VERSION 5.7 ;
  NOWIREEXTENSIONATPIN ON ;
  DIVIDERCHAR "/" ;
  BUSBITCHARS "[]" ;
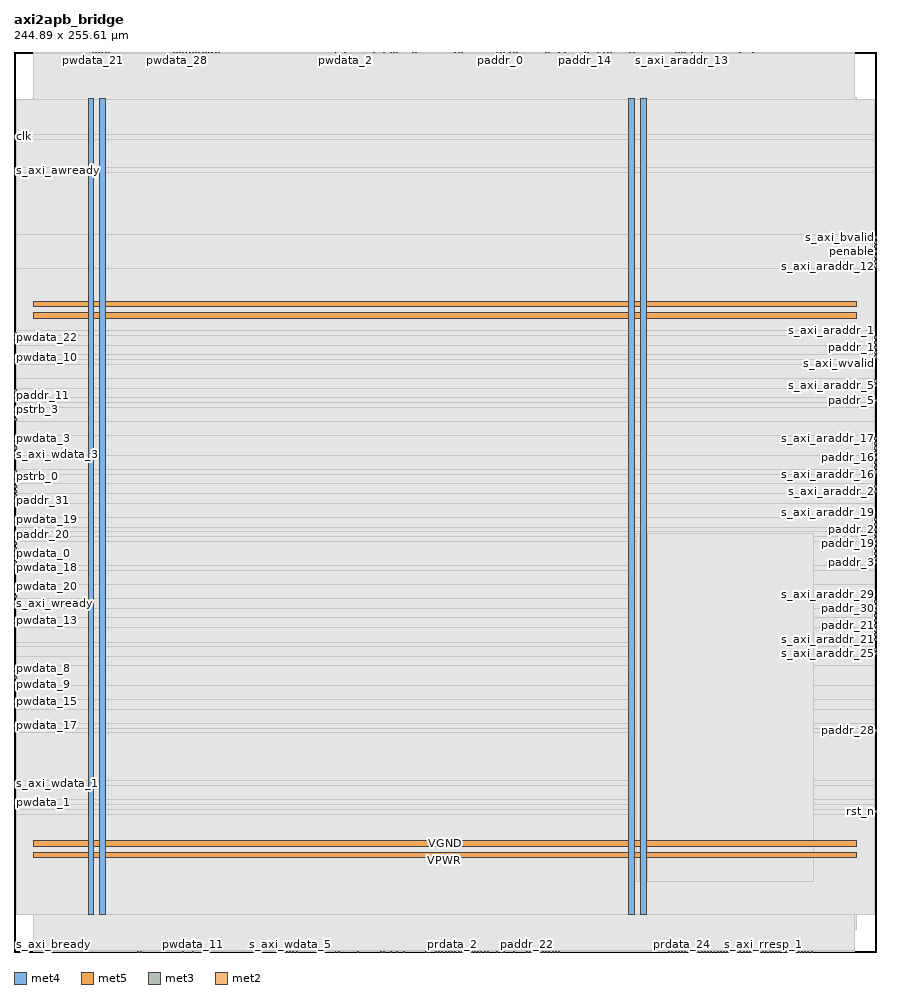
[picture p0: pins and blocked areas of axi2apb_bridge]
MACRO axi2apb_bridge
  CLASS BLOCK ;
  FOREIGN axi2apb_bridge ;
  ORIGIN 0.000 0.000 ;
  SIZE 244.890 BY 255.610 ;
  PIN VGND
    DIRECTION INOUT ;
    USE GROUND ;
    PORT
      LAYER met4 ;
        RECT 24.340 10.640 25.940 242.320 ;
    END
    PORT
      LAYER met4 ;
        RECT 177.940 10.640 179.540 242.320 ;
    END
    PORT
      LAYER met5 ;
        RECT 5.520 30.030 239.200 31.630 ;
    END
    PORT
      LAYER met5 ;
        RECT 5.520 183.210 239.200 184.810 ;
    END
  END VGND
  PIN VPWR
    DIRECTION INOUT ;
    USE POWER ;
    PORT
      LAYER met4 ;
        RECT 21.040 10.640 22.640 242.320 ;
    END
    PORT
      LAYER met4 ;
        RECT 174.640 10.640 176.240 242.320 ;
    END
    PORT
      LAYER met5 ;
        RECT 5.520 26.730 239.200 28.330 ;
    END
    PORT
      LAYER met5 ;
        RECT 5.520 179.910 239.200 181.510 ;
    END
  END VPWR
  PIN clk
    DIRECTION INPUT ;
    USE SIGNAL ;
    ANTENNAGATEAREA 1.286700 ;
    ANTENNADIFFAREA 0.434700 ;
    PORT
      LAYER met3 ;
        RECT 0.000 231.240 0.600 231.840 ;
    END
  END clk
  PIN paddr_0
    DIRECTION OUTPUT ;
    USE SIGNAL ;
    ANTENNAGATEAREA 0.434700 ;
    ANTENNADIFFAREA 1.137600 ;
    PORT
      LAYER met2 ;
        RECT 138.090 255.330 138.370 255.610 ;
    END
  END paddr_0
  PIN paddr_1
    DIRECTION OUTPUT ;
    USE SIGNAL ;
    ANTENNAGATEAREA 0.434700 ;
    ANTENNADIFFAREA 1.137600 ;
    PORT
      LAYER met3 ;
        RECT 244.290 171.400 244.890 172.000 ;
    END
  END paddr_1
  PIN paddr_10
    DIRECTION OUTPUT ;
    USE SIGNAL ;
    ANTENNAGATEAREA 0.434700 ;
    ANTENNADIFFAREA 1.137600 ;
    PORT
      LAYER met2 ;
        RECT 125.210 255.330 125.490 255.610 ;
    END
  END paddr_10
  PIN paddr_11
    DIRECTION OUTPUT ;
    USE SIGNAL ;
    ANTENNAGATEAREA 0.434700 ;
    ANTENNADIFFAREA 1.137600 ;
    PORT
      LAYER met3 ;
        RECT 0.000 157.800 0.600 158.400 ;
    END
  END paddr_11
  PIN paddr_12
    DIRECTION OUTPUT ;
    USE SIGNAL ;
    ANTENNAGATEAREA 0.434700 ;
    ANTENNADIFFAREA 1.137600 ;
    PORT
      LAYER met2 ;
        RECT 209.850 255.330 210.130 255.610 ;
    END
  END paddr_12
  PIN paddr_13
    DIRECTION OUTPUT ;
    USE SIGNAL ;
    ANTENNAGATEAREA 0.434700 ;
    ANTENNADIFFAREA 1.137600 ;
    PORT
      LAYER met2 ;
        RECT 206.170 255.330 206.450 255.610 ;
    END
  END paddr_13
  PIN paddr_14
    DIRECTION OUTPUT ;
    USE SIGNAL ;
    ANTENNAGATEAREA 0.434700 ;
    ANTENNADIFFAREA 1.137600 ;
    PORT
      LAYER met2 ;
        RECT 162.010 255.330 162.290 255.610 ;
    END
  END paddr_14
  PIN paddr_15
    DIRECTION OUTPUT ;
    USE SIGNAL ;
    ANTENNAGATEAREA 0.434700 ;
    ANTENNADIFFAREA 1.137600 ;
    PORT
      LAYER met2 ;
        RECT 151.890 255.330 152.170 255.610 ;
    END
  END paddr_15
  PIN paddr_16
    DIRECTION OUTPUT ;
    USE SIGNAL ;
    ANTENNAGATEAREA 0.434700 ;
    ANTENNADIFFAREA 1.137600 ;
    PORT
      LAYER met3 ;
        RECT 244.290 140.120 244.890 140.720 ;
    END
  END paddr_16
  PIN paddr_17
    DIRECTION OUTPUT ;
    USE SIGNAL ;
    ANTENNAGATEAREA 0.434700 ;
    ANTENNADIFFAREA 1.137600 ;
    PORT
      LAYER met2 ;
        RECT 150.970 255.330 151.250 255.610 ;
    END
  END paddr_17
  PIN paddr_18
    DIRECTION OUTPUT ;
    USE SIGNAL ;
    ANTENNAGATEAREA 0.434700 ;
    ANTENNADIFFAREA 1.137600 ;
    PORT
      LAYER met2 ;
        RECT 168.450 255.330 168.730 255.610 ;
    END
  END paddr_18
  PIN paddr_19
    DIRECTION OUTPUT ;
    USE SIGNAL ;
    ANTENNAGATEAREA 0.434700 ;
    ANTENNADIFFAREA 1.137600 ;
    PORT
      LAYER met3 ;
        RECT 244.290 115.640 244.890 116.240 ;
    END
  END paddr_19
  PIN paddr_2
    DIRECTION OUTPUT ;
    USE SIGNAL ;
    ANTENNAGATEAREA 0.434700 ;
    ANTENNADIFFAREA 1.137600 ;
    PORT
      LAYER met3 ;
        RECT 244.290 119.720 244.890 120.320 ;
    END
  END paddr_2
  PIN paddr_20
    DIRECTION OUTPUT ;
    USE SIGNAL ;
    ANTENNAGATEAREA 0.434700 ;
    ANTENNADIFFAREA 1.137600 ;
    PORT
      LAYER met3 ;
        RECT 0.000 118.360 0.600 118.960 ;
    END
  END paddr_20
  PIN paddr_21
    DIRECTION OUTPUT ;
    USE SIGNAL ;
    ANTENNAGATEAREA 0.434700 ;
    ANTENNADIFFAREA 1.137600 ;
    PORT
      LAYER met3 ;
        RECT 244.290 92.520 244.890 93.120 ;
    END
  END paddr_21
  PIN paddr_22
    DIRECTION OUTPUT ;
    USE SIGNAL ;
    ANTENNAGATEAREA 0.434700 ;
    ANTENNADIFFAREA 1.137600 ;
    PORT
      LAYER met2 ;
        RECT 145.450 0.000 145.730 0.280 ;
    END
  END paddr_22
  PIN paddr_23
    DIRECTION OUTPUT ;
    USE SIGNAL ;
    ANTENNAGATEAREA 0.434700 ;
    ANTENNADIFFAREA 1.137600 ;
    PORT
      LAYER met2 ;
        RECT 110.490 0.000 110.770 0.280 ;
    END
  END paddr_23
  PIN paddr_24
    DIRECTION OUTPUT ;
    USE SIGNAL ;
    ANTENNAGATEAREA 0.434700 ;
    ANTENNADIFFAREA 1.137600 ;
    PORT
      LAYER met2 ;
        RECT 226.410 0.000 226.690 0.280 ;
    END
  END paddr_24
  PIN paddr_25
    DIRECTION OUTPUT ;
    USE SIGNAL ;
    ANTENNAGATEAREA 0.434700 ;
    ANTENNADIFFAREA 1.137600 ;
    PORT
      LAYER met3 ;
        RECT 244.290 91.160 244.890 91.760 ;
    END
  END paddr_25
  PIN paddr_26
    DIRECTION OUTPUT ;
    USE SIGNAL ;
    ANTENNAGATEAREA 0.434700 ;
    ANTENNADIFFAREA 1.137600 ;
    PORT
      LAYER met2 ;
        RECT 91.170 0.000 91.450 0.280 ;
    END
  END paddr_26
  PIN paddr_27
    DIRECTION OUTPUT ;
    USE SIGNAL ;
    ANTENNAGATEAREA 0.434700 ;
    ANTENNADIFFAREA 1.137600 ;
    PORT
      LAYER met2 ;
        RECT 87.490 0.000 87.770 0.280 ;
    END
  END paddr_27
  PIN paddr_28
    DIRECTION OUTPUT ;
    USE SIGNAL ;
    ANTENNAGATEAREA 0.434700 ;
    ANTENNADIFFAREA 1.137600 ;
    PORT
      LAYER met3 ;
        RECT 244.290 62.600 244.890 63.200 ;
    END
  END paddr_28
  PIN paddr_29
    DIRECTION OUTPUT ;
    USE SIGNAL ;
    ANTENNAGATEAREA 0.434700 ;
    ANTENNADIFFAREA 1.137600 ;
    PORT
      LAYER met2 ;
        RECT 133.490 0.000 133.770 0.280 ;
    END
  END paddr_29
  PIN paddr_3
    DIRECTION OUTPUT ;
    USE SIGNAL ;
    ANTENNAGATEAREA 0.434700 ;
    ANTENNADIFFAREA 1.137600 ;
    PORT
      LAYER met3 ;
        RECT 244.290 110.200 244.890 110.800 ;
    END
  END paddr_3
  PIN paddr_30
    DIRECTION OUTPUT ;
    USE SIGNAL ;
    ANTENNAGATEAREA 0.434700 ;
    ANTENNADIFFAREA 1.137600 ;
    PORT
      LAYER met3 ;
        RECT 244.290 95.240 244.890 95.840 ;
    END
  END paddr_30
  PIN paddr_31
    DIRECTION OUTPUT ;
    USE SIGNAL ;
    ANTENNAGATEAREA 0.434700 ;
    ANTENNADIFFAREA 1.137600 ;
    PORT
      LAYER met3 ;
        RECT 0.000 127.880 0.600 128.480 ;
    END
  END paddr_31
  PIN paddr_4
    DIRECTION OUTPUT ;
    USE SIGNAL ;
    ANTENNAGATEAREA 0.434700 ;
    ANTENNADIFFAREA 1.137600 ;
    PORT
      LAYER met3 ;
        RECT 244.290 114.280 244.890 114.880 ;
    END
  END paddr_4
  PIN paddr_5
    DIRECTION OUTPUT ;
    USE SIGNAL ;
    ANTENNAGATEAREA 0.434700 ;
    ANTENNADIFFAREA 1.137600 ;
    PORT
      LAYER met3 ;
        RECT 244.290 156.440 244.890 157.040 ;
    END
  END paddr_5
  PIN paddr_6
    DIRECTION OUTPUT ;
    USE SIGNAL ;
    ANTENNAGATEAREA 0.434700 ;
    ANTENNADIFFAREA 1.137600 ;
    PORT
      LAYER met2 ;
        RECT 45.170 255.330 45.450 255.610 ;
    END
  END paddr_6
  PIN paddr_7
    DIRECTION OUTPUT ;
    USE SIGNAL ;
    ANTENNAGATEAREA 0.434700 ;
    ANTENNADIFFAREA 1.137600 ;
    PORT
      LAYER met2 ;
        RECT 102.210 255.330 102.490 255.610 ;
    END
  END paddr_7
  PIN paddr_8
    DIRECTION OUTPUT ;
    USE SIGNAL ;
    ANTENNAGATEAREA 0.434700 ;
    ANTENNADIFFAREA 1.137600 ;
    PORT
      LAYER met3 ;
        RECT 244.290 138.760 244.890 139.360 ;
    END
  END paddr_8
  PIN paddr_9
    DIRECTION OUTPUT ;
    USE SIGNAL ;
    ANTENNAGATEAREA 0.434700 ;
    ANTENNADIFFAREA 1.137600 ;
    PORT
      LAYER met2 ;
        RECT 142.690 255.330 142.970 255.610 ;
    END
  END paddr_9
  PIN penable
    DIRECTION OUTPUT ;
    USE SIGNAL ;
    ANTENNAGATEAREA 0.434700 ;
    ANTENNADIFFAREA 1.137600 ;
    PORT
      LAYER met3 ;
        RECT 244.290 198.600 244.890 199.200 ;
    END
  END penable
  PIN prdata_0
    DIRECTION INPUT ;
    USE SIGNAL ;
    ANTENNAGATEAREA 0.647700 ;
    ANTENNADIFFAREA 0.434700 ;
    PORT
      LAYER met2 ;
        RECT 204.330 0.000 204.610 0.280 ;
    END
  END prdata_0
  PIN prdata_1
    DIRECTION INPUT ;
    USE SIGNAL ;
    ANTENNAGATEAREA 0.647700 ;
    ANTENNADIFFAREA 0.434700 ;
    PORT
      LAYER met2 ;
        RECT 185.930 0.000 186.210 0.280 ;
    END
  END prdata_1
  PIN prdata_10
    DIRECTION INPUT ;
    USE SIGNAL ;
    ANTENNAGATEAREA 0.647700 ;
    ANTENNADIFFAREA 0.434700 ;
    PORT
      LAYER met2 ;
        RECT 132.570 0.000 132.850 0.280 ;
    END
  END prdata_10
  PIN prdata_11
    DIRECTION INPUT ;
    USE SIGNAL ;
    ANTENNAGATEAREA 0.647700 ;
    ANTENNADIFFAREA 0.434700 ;
    PORT
      LAYER met2 ;
        RECT 119.690 0.000 119.970 0.280 ;
    END
  END prdata_11
  PIN prdata_12
    DIRECTION INPUT ;
    USE SIGNAL ;
    ANTENNAGATEAREA 0.647700 ;
    ANTENNADIFFAREA 0.434700 ;
    PORT
      LAYER met2 ;
        RECT 225.490 0.000 225.770 0.280 ;
    END
  END prdata_12
  PIN prdata_13
    DIRECTION INPUT ;
    USE SIGNAL ;
    ANTENNAGATEAREA 0.647700 ;
    ANTENNADIFFAREA 0.434700 ;
    PORT
      LAYER met2 ;
        RECT 122.450 0.000 122.730 0.280 ;
    END
  END prdata_13
  PIN prdata_14
    DIRECTION INPUT ;
    USE SIGNAL ;
    ANTENNAGATEAREA 0.647700 ;
    ANTENNADIFFAREA 0.434700 ;
    PORT
      LAYER met2 ;
        RECT 127.050 0.000 127.330 0.280 ;
    END
  END prdata_14
  PIN prdata_15
    DIRECTION INPUT ;
    USE SIGNAL ;
    ANTENNAGATEAREA 0.647700 ;
    ANTENNADIFFAREA 0.434700 ;
    PORT
      LAYER met2 ;
        RECT 205.250 0.000 205.530 0.280 ;
    END
  END prdata_15
  PIN prdata_16
    DIRECTION INPUT ;
    USE SIGNAL ;
    ANTENNAGATEAREA 0.647700 ;
    ANTENNADIFFAREA 0.434700 ;
    PORT
      LAYER met2 ;
        RECT 196.050 0.000 196.330 0.280 ;
    END
  END prdata_16
  PIN prdata_17
    DIRECTION INPUT ;
    USE SIGNAL ;
    ANTENNAGATEAREA 0.647700 ;
    ANTENNADIFFAREA 0.434700 ;
    PORT
      LAYER met2 ;
        RECT 127.970 0.000 128.250 0.280 ;
    END
  END prdata_17
  PIN prdata_18
    DIRECTION INPUT ;
    USE SIGNAL ;
    ANTENNAGATEAREA 0.647700 ;
    ANTENNADIFFAREA 0.434700 ;
    PORT
      LAYER met2 ;
        RECT 203.410 0.000 203.690 0.280 ;
    END
  END prdata_18
  PIN prdata_19
    DIRECTION INPUT ;
    USE SIGNAL ;
    ANTENNAGATEAREA 0.647700 ;
    ANTENNADIFFAREA 0.434700 ;
    PORT
      LAYER met2 ;
        RECT 224.570 0.000 224.850 0.280 ;
    END
  END prdata_19
  PIN prdata_2
    DIRECTION INPUT ;
    USE SIGNAL ;
    ANTENNAGATEAREA 0.647700 ;
    ANTENNADIFFAREA 0.434700 ;
    PORT
      LAYER met2 ;
        RECT 124.290 0.000 124.570 0.280 ;
    END
  END prdata_2
  PIN prdata_20
    DIRECTION INPUT ;
    USE SIGNAL ;
    ANTENNAGATEAREA 0.647700 ;
    ANTENNADIFFAREA 0.434700 ;
    PORT
      LAYER met2 ;
        RECT 150.970 0.000 151.250 0.280 ;
    END
  END prdata_20
  PIN prdata_21
    DIRECTION INPUT ;
    USE SIGNAL ;
    ANTENNAGATEAREA 0.647700 ;
    ANTENNADIFFAREA 0.434700 ;
    PORT
      LAYER met2 ;
        RECT 194.210 0.000 194.490 0.280 ;
    END
  END prdata_21
  PIN prdata_22
    DIRECTION INPUT ;
    USE SIGNAL ;
    ANTENNAGATEAREA 0.647700 ;
    ANTENNADIFFAREA 0.434700 ;
    PORT
      LAYER met2 ;
        RECT 220.890 0.000 221.170 0.280 ;
    END
  END prdata_22
  PIN prdata_23
    DIRECTION INPUT ;
    USE SIGNAL ;
    ANTENNAGATEAREA 0.647700 ;
    ANTENNADIFFAREA 0.434700 ;
    PORT
      LAYER met2 ;
        RECT 187.770 0.000 188.050 0.280 ;
    END
  END prdata_23
  PIN prdata_24
    DIRECTION INPUT ;
    USE SIGNAL ;
    ANTENNAGATEAREA 0.647700 ;
    ANTENNADIFFAREA 0.434700 ;
    PORT
      LAYER met2 ;
        RECT 189.610 0.000 189.890 0.280 ;
    END
  END prdata_24
  PIN prdata_25
    DIRECTION INPUT ;
    USE SIGNAL ;
    ANTENNAGATEAREA 0.647700 ;
    ANTENNADIFFAREA 0.434700 ;
    PORT
      LAYER met2 ;
        RECT 199.730 0.000 200.010 0.280 ;
    END
  END prdata_25
  PIN prdata_26
    DIRECTION INPUT ;
    USE SIGNAL ;
    ANTENNAGATEAREA 0.647700 ;
    ANTENNADIFFAREA 0.434700 ;
    PORT
      LAYER met2 ;
        RECT 131.650 0.000 131.930 0.280 ;
    END
  END prdata_26
  PIN prdata_27
    DIRECTION INPUT ;
    USE SIGNAL ;
    ANTENNAGATEAREA 0.647700 ;
    ANTENNADIFFAREA 0.434700 ;
    PORT
      LAYER met2 ;
        RECT 123.370 0.000 123.650 0.280 ;
    END
  END prdata_27
  PIN prdata_28
    DIRECTION INPUT ;
    USE SIGNAL ;
    ANTENNAGATEAREA 0.647700 ;
    ANTENNADIFFAREA 0.434700 ;
    PORT
      LAYER met2 ;
        RECT 202.490 0.000 202.770 0.280 ;
    END
  END prdata_28
  PIN prdata_29
    DIRECTION INPUT ;
    USE SIGNAL ;
    ANTENNAGATEAREA 0.647700 ;
    ANTENNADIFFAREA 0.434700 ;
    PORT
      LAYER met2 ;
        RECT 208.930 0.000 209.210 0.280 ;
    END
  END prdata_29
  PIN prdata_3
    DIRECTION INPUT ;
    USE SIGNAL ;
    ANTENNAGATEAREA 0.647700 ;
    ANTENNADIFFAREA 0.434700 ;
    PORT
      LAYER met2 ;
        RECT 137.170 0.000 137.450 0.280 ;
    END
  END prdata_3
  PIN prdata_30
    DIRECTION INPUT ;
    USE SIGNAL ;
    ANTENNAGATEAREA 0.647700 ;
    ANTENNADIFFAREA 0.434700 ;
    PORT
      LAYER met2 ;
        RECT 149.130 0.000 149.410 0.280 ;
    END
  END prdata_30
  PIN prdata_31
    DIRECTION INPUT ;
    USE SIGNAL ;
    ANTENNAGATEAREA 0.647700 ;
    ANTENNADIFFAREA 0.434700 ;
    PORT
      LAYER met2 ;
        RECT 206.170 0.000 206.450 0.280 ;
    END
  END prdata_31
  PIN prdata_4
    DIRECTION INPUT ;
    USE SIGNAL ;
    ANTENNAGATEAREA 0.647700 ;
    ANTENNADIFFAREA 0.434700 ;
    PORT
      LAYER met2 ;
        RECT 147.290 0.000 147.570 0.280 ;
    END
  END prdata_4
  PIN prdata_5
    DIRECTION INPUT ;
    USE SIGNAL ;
    ANTENNAGATEAREA 0.647700 ;
    ANTENNADIFFAREA 0.434700 ;
    PORT
      LAYER met2 ;
        RECT 197.890 0.000 198.170 0.280 ;
    END
  END prdata_5
  PIN prdata_6
    DIRECTION INPUT ;
    USE SIGNAL ;
    ANTENNAGATEAREA 0.647700 ;
    ANTENNADIFFAREA 0.434700 ;
    PORT
      LAYER met2 ;
        RECT 198.810 0.000 199.090 0.280 ;
    END
  END prdata_6
  PIN prdata_7
    DIRECTION INPUT ;
    USE SIGNAL ;
    ANTENNAGATEAREA 0.647700 ;
    ANTENNADIFFAREA 0.434700 ;
    PORT
      LAYER met2 ;
        RECT 210.770 0.000 211.050 0.280 ;
    END
  END prdata_7
  PIN prdata_8
    DIRECTION INPUT ;
    USE SIGNAL ;
    ANTENNAGATEAREA 0.647700 ;
    ANTENNADIFFAREA 0.434700 ;
    PORT
      LAYER met2 ;
        RECT 154.650 0.000 154.930 0.280 ;
    END
  END prdata_8
  PIN prdata_9
    DIRECTION INPUT ;
    USE SIGNAL ;
    ANTENNAGATEAREA 0.647700 ;
    ANTENNADIFFAREA 0.434700 ;
    PORT
      LAYER met2 ;
        RECT 146.370 0.000 146.650 0.280 ;
    END
  END prdata_9
  PIN pready
    DIRECTION INPUT ;
    USE SIGNAL ;
    ANTENNAGATEAREA 0.647700 ;
    ANTENNADIFFAREA 0.434700 ;
    PORT
      LAYER met2 ;
        RECT 196.970 0.000 197.250 0.280 ;
    END
  END pready
  PIN psel_0
    DIRECTION OUTPUT ;
    USE SIGNAL ;
    ANTENNAGATEAREA 0.434700 ;
    ANTENNADIFFAREA 1.137600 ;
    PORT
      LAYER met2 ;
        RECT 188.690 255.330 188.970 255.610 ;
    END
  END psel_0
  PIN psel_1
    DIRECTION OUTPUT ;
    USE SIGNAL ;
    ANTENNAGATEAREA 0.434700 ;
    ANTENNADIFFAREA 1.137600 ;
    PORT
      LAYER met2 ;
        RECT 190.530 255.330 190.810 255.610 ;
    END
  END psel_1
  PIN psel_2
    DIRECTION OUTPUT ;
    USE SIGNAL ;
    ANTENNAGATEAREA 0.434700 ;
    ANTENNADIFFAREA 1.137600 ;
    PORT
      LAYER met2 ;
        RECT 174.890 255.330 175.170 255.610 ;
    END
  END psel_2
  PIN psel_3
    DIRECTION OUTPUT ;
    USE SIGNAL ;
    ANTENNAGATEAREA 0.434700 ;
    ANTENNADIFFAREA 1.137600 ;
    PORT
      LAYER met2 ;
        RECT 175.810 255.330 176.090 255.610 ;
    END
  END psel_3
  PIN psel_4
    DIRECTION OUTPUT ;
    USE SIGNAL ;
    ANTENNAGATEAREA 0.434700 ;
    ANTENNADIFFAREA 1.137600 ;
    PORT
      LAYER met2 ;
        RECT 192.370 255.330 192.650 255.610 ;
    END
  END psel_4
  PIN psel_5
    DIRECTION OUTPUT ;
    USE SIGNAL ;
    ANTENNAGATEAREA 0.434700 ;
    ANTENNADIFFAREA 1.137600 ;
    PORT
      LAYER met2 ;
        RECT 195.130 255.330 195.410 255.610 ;
    END
  END psel_5
  PIN pslverr
    DIRECTION INPUT ;
    USE SIGNAL ;
    ANTENNAGATEAREA 0.647700 ;
    ANTENNADIFFAREA 0.434700 ;
    PORT
      LAYER met2 ;
        RECT 219.970 0.000 220.250 0.280 ;
    END
  END pslverr
  PIN pstrb_0
    DIRECTION OUTPUT ;
    USE SIGNAL ;
    ANTENNAGATEAREA 0.434700 ;
    ANTENNADIFFAREA 1.137600 ;
    PORT
      LAYER met3 ;
        RECT 0.000 134.680 0.600 135.280 ;
    END
  END pstrb_0
  PIN pstrb_1
    DIRECTION OUTPUT ;
    USE SIGNAL ;
    ANTENNAGATEAREA 0.434700 ;
    ANTENNADIFFAREA 1.137600 ;
    PORT
      LAYER met3 ;
        RECT 0.000 131.960 0.600 132.560 ;
    END
  END pstrb_1
  PIN pstrb_2
    DIRECTION OUTPUT ;
    USE SIGNAL ;
    ANTENNAGATEAREA 0.434700 ;
    ANTENNADIFFAREA 1.137600 ;
    PORT
      LAYER met3 ;
        RECT 0.000 156.440 0.600 157.040 ;
    END
  END pstrb_2
  PIN pstrb_3
    DIRECTION OUTPUT ;
    USE SIGNAL ;
    ANTENNAGATEAREA 0.434700 ;
    ANTENNADIFFAREA 1.137600 ;
    PORT
      LAYER met3 ;
        RECT 0.000 153.720 0.600 154.320 ;
    END
  END pstrb_3
  PIN pwdata_0
    DIRECTION OUTPUT ;
    USE SIGNAL ;
    ANTENNAGATEAREA 0.434700 ;
    ANTENNADIFFAREA 1.137600 ;
    PORT
      LAYER met3 ;
        RECT 0.000 112.920 0.600 113.520 ;
    END
  END pwdata_0
  PIN pwdata_1
    DIRECTION OUTPUT ;
    USE SIGNAL ;
    ANTENNAGATEAREA 0.434700 ;
    ANTENNADIFFAREA 1.137600 ;
    PORT
      LAYER met3 ;
        RECT 0.000 42.200 0.600 42.800 ;
    END
  END pwdata_1
  PIN pwdata_10
    DIRECTION OUTPUT ;
    USE SIGNAL ;
    ANTENNAGATEAREA 0.434700 ;
    ANTENNADIFFAREA 1.137600 ;
    PORT
      LAYER met3 ;
        RECT 0.000 168.680 0.600 169.280 ;
    END
  END pwdata_10
  PIN pwdata_11
    DIRECTION OUTPUT ;
    USE SIGNAL ;
    ANTENNAGATEAREA 0.434700 ;
    ANTENNADIFFAREA 1.137600 ;
    PORT
      LAYER met2 ;
        RECT 50.690 0.000 50.970 0.280 ;
    END
  END pwdata_11
  PIN pwdata_12
    DIRECTION OUTPUT ;
    USE SIGNAL ;
    ANTENNAGATEAREA 0.434700 ;
    ANTENNADIFFAREA 1.137600 ;
    PORT
      LAYER met3 ;
        RECT 0.000 99.320 0.600 99.920 ;
    END
  END pwdata_12
  PIN pwdata_13
    DIRECTION OUTPUT ;
    USE SIGNAL ;
    ANTENNAGATEAREA 0.434700 ;
    ANTENNADIFFAREA 1.137600 ;
    PORT
      LAYER met3 ;
        RECT 0.000 93.880 0.600 94.480 ;
    END
  END pwdata_13
  PIN pwdata_14
    DIRECTION OUTPUT ;
    USE SIGNAL ;
    ANTENNAGATEAREA 0.434700 ;
    ANTENNADIFFAREA 1.137600 ;
    PORT
      LAYER met2 ;
        RECT 35.050 0.000 35.330 0.280 ;
    END
  END pwdata_14
  PIN pwdata_15
    DIRECTION OUTPUT ;
    USE SIGNAL ;
    ANTENNAGATEAREA 0.434700 ;
    ANTENNADIFFAREA 1.137600 ;
    PORT
      LAYER met3 ;
        RECT 0.000 70.760 0.600 71.360 ;
    END
  END pwdata_15
  PIN pwdata_16
    DIRECTION OUTPUT ;
    USE SIGNAL ;
    ANTENNAGATEAREA 0.434700 ;
    ANTENNADIFFAREA 1.137600 ;
    PORT
      LAYER met3 ;
        RECT 0.000 141.480 0.600 142.080 ;
    END
  END pwdata_16
  PIN pwdata_17
    DIRECTION OUTPUT ;
    USE SIGNAL ;
    ANTENNAGATEAREA 0.434700 ;
    ANTENNADIFFAREA 1.137600 ;
    PORT
      LAYER met3 ;
        RECT 0.000 63.960 0.600 64.560 ;
    END
  END pwdata_17
  PIN pwdata_18
    DIRECTION OUTPUT ;
    USE SIGNAL ;
    ANTENNAGATEAREA 0.434700 ;
    ANTENNADIFFAREA 1.137600 ;
    PORT
      LAYER met3 ;
        RECT 0.000 108.840 0.600 109.440 ;
    END
  END pwdata_18
  PIN pwdata_19
    DIRECTION OUTPUT ;
    USE SIGNAL ;
    ANTENNAGATEAREA 0.434700 ;
    ANTENNADIFFAREA 1.137600 ;
    PORT
      LAYER met3 ;
        RECT 0.000 122.440 0.600 123.040 ;
    END
  END pwdata_19
  PIN pwdata_2
    DIRECTION OUTPUT ;
    USE SIGNAL ;
    ANTENNAGATEAREA 0.434700 ;
    ANTENNADIFFAREA 1.137600 ;
    PORT
      LAYER met2 ;
        RECT 93.930 255.330 94.210 255.610 ;
    END
  END pwdata_2
  PIN pwdata_20
    DIRECTION OUTPUT ;
    USE SIGNAL ;
    ANTENNAGATEAREA 0.434700 ;
    ANTENNADIFFAREA 1.137600 ;
    PORT
      LAYER met3 ;
        RECT 0.000 103.400 0.600 104.000 ;
    END
  END pwdata_20
  PIN pwdata_21
    DIRECTION OUTPUT ;
    USE SIGNAL ;
    ANTENNAGATEAREA 0.434700 ;
    ANTENNADIFFAREA 1.137600 ;
    PORT
      LAYER met2 ;
        RECT 22.170 255.330 22.450 255.610 ;
    END
  END pwdata_21
  PIN pwdata_22
    DIRECTION OUTPUT ;
    USE SIGNAL ;
    ANTENNAGATEAREA 0.434700 ;
    ANTENNADIFFAREA 1.137600 ;
    PORT
      LAYER met3 ;
        RECT 0.000 174.120 0.600 174.720 ;
    END
  END pwdata_22
  PIN pwdata_23
    DIRECTION OUTPUT ;
    USE SIGNAL ;
    ANTENNAGATEAREA 0.434700 ;
    ANTENNADIFFAREA 1.137600 ;
    PORT
      LAYER met2 ;
        RECT 26.770 255.330 27.050 255.610 ;
    END
  END pwdata_23
  PIN pwdata_24
    DIRECTION OUTPUT ;
    USE SIGNAL ;
    ANTENNAGATEAREA 0.434700 ;
    ANTENNADIFFAREA 1.137600 ;
    PORT
      LAYER met2 ;
        RECT 25.850 255.330 26.130 255.610 ;
    END
  END pwdata_24
  PIN pwdata_25
    DIRECTION OUTPUT ;
    USE SIGNAL ;
    ANTENNAGATEAREA 0.434700 ;
    ANTENNADIFFAREA 1.137600 ;
    PORT
      LAYER met2 ;
        RECT 55.290 255.330 55.570 255.610 ;
    END
  END pwdata_25
  PIN pwdata_26
    DIRECTION OUTPUT ;
    USE SIGNAL ;
    ANTENNAGATEAREA 0.434700 ;
    ANTENNADIFFAREA 1.137600 ;
    PORT
      LAYER met2 ;
        RECT 47.010 255.330 47.290 255.610 ;
    END
  END pwdata_26
  PIN pwdata_27
    DIRECTION OUTPUT ;
    USE SIGNAL ;
    ANTENNAGATEAREA 0.434700 ;
    ANTENNADIFFAREA 1.137600 ;
    PORT
      LAYER met2 ;
        RECT 56.210 255.330 56.490 255.610 ;
    END
  END pwdata_27
  PIN pwdata_28
    DIRECTION OUTPUT ;
    USE SIGNAL ;
    ANTENNAGATEAREA 0.434700 ;
    ANTENNADIFFAREA 1.137600 ;
    PORT
      LAYER met2 ;
        RECT 46.090 255.330 46.370 255.610 ;
    END
  END pwdata_28
  PIN pwdata_29
    DIRECTION OUTPUT ;
    USE SIGNAL ;
    ANTENNAGATEAREA 0.434700 ;
    ANTENNADIFFAREA 1.137600 ;
    PORT
      LAYER met2 ;
        RECT 47.930 255.330 48.210 255.610 ;
    END
  END pwdata_29
  PIN pwdata_3
    DIRECTION OUTPUT ;
    USE SIGNAL ;
    ANTENNAGATEAREA 0.434700 ;
    ANTENNADIFFAREA 1.137600 ;
    PORT
      LAYER met3 ;
        RECT 0.000 145.560 0.600 146.160 ;
    END
  END pwdata_3
  PIN pwdata_30
    DIRECTION OUTPUT ;
    USE SIGNAL ;
    ANTENNAGATEAREA 0.434700 ;
    ANTENNADIFFAREA 1.137600 ;
    PORT
      LAYER met2 ;
        RECT 54.370 255.330 54.650 255.610 ;
    END
  END pwdata_30
  PIN pwdata_31
    DIRECTION OUTPUT ;
    USE SIGNAL ;
    ANTENNAGATEAREA 0.434700 ;
    ANTENNADIFFAREA 1.137600 ;
    PORT
      LAYER met2 ;
        RECT 49.770 255.330 50.050 255.610 ;
    END
  END pwdata_31
  PIN pwdata_4
    DIRECTION OUTPUT ;
    USE SIGNAL ;
    ANTENNAGATEAREA 0.434700 ;
    ANTENNADIFFAREA 1.137600 ;
    PORT
      LAYER met2 ;
        RECT 97.610 0.000 97.890 0.280 ;
    END
  END pwdata_4
  PIN pwdata_5
    DIRECTION OUTPUT ;
    USE SIGNAL ;
    ANTENNAGATEAREA 0.434700 ;
    ANTENNADIFFAREA 1.137600 ;
    PORT
      LAYER met2 ;
        RECT 80.130 0.000 80.410 0.280 ;
    END
  END pwdata_5
  PIN pwdata_6
    DIRECTION OUTPUT ;
    USE SIGNAL ;
    ANTENNAGATEAREA 0.434700 ;
    ANTENNADIFFAREA 1.137600 ;
    PORT
      LAYER met2 ;
        RECT 70.010 0.000 70.290 0.280 ;
    END
  END pwdata_6
  PIN pwdata_7
    DIRECTION OUTPUT ;
    USE SIGNAL ;
    ANTENNAGATEAREA 0.434700 ;
    ANTENNADIFFAREA 1.137600 ;
    PORT
      LAYER met2 ;
        RECT 77.370 0.000 77.650 0.280 ;
    END
  END pwdata_7
  PIN pwdata_8
    DIRECTION OUTPUT ;
    USE SIGNAL ;
    ANTENNAGATEAREA 0.434700 ;
    ANTENNADIFFAREA 1.137600 ;
    PORT
      LAYER met3 ;
        RECT 0.000 80.280 0.600 80.880 ;
    END
  END pwdata_8
  PIN pwdata_9
    DIRECTION OUTPUT ;
    USE SIGNAL ;
    ANTENNAGATEAREA 0.434700 ;
    ANTENNADIFFAREA 1.137600 ;
    PORT
      LAYER met3 ;
        RECT 0.000 77.560 0.600 78.160 ;
    END
  END pwdata_9
  PIN pwrite
    DIRECTION OUTPUT ;
    USE SIGNAL ;
    ANTENNAGATEAREA 0.434700 ;
    ANTENNADIFFAREA 1.137600 ;
    PORT
      LAYER met3 ;
        RECT 0.000 175.480 0.600 176.080 ;
    END
  END pwrite
  PIN rst_n
    DIRECTION INPUT ;
    USE SIGNAL ;
    ANTENNAGATEAREA 0.647700 ;
    ANTENNADIFFAREA 0.434700 ;
    PORT
      LAYER met3 ;
        RECT 244.290 39.480 244.890 40.080 ;
    END
  END rst_n
  PIN s_axi_araddr_0
    DIRECTION INPUT ;
    USE SIGNAL ;
    ANTENNAGATEAREA 0.647700 ;
    ANTENNADIFFAREA 0.434700 ;
    PORT
      LAYER met2 ;
        RECT 139.010 255.330 139.290 255.610 ;
    END
  END s_axi_araddr_0
  PIN s_axi_araddr_1
    DIRECTION INPUT ;
    USE SIGNAL ;
    ANTENNAGATEAREA 0.647700 ;
    ANTENNADIFFAREA 0.434700 ;
    PORT
      LAYER met3 ;
        RECT 244.290 174.120 244.890 174.720 ;
    END
  END s_axi_araddr_1
  PIN s_axi_araddr_10
    DIRECTION INPUT ;
    USE SIGNAL ;
    ANTENNAGATEAREA 0.647700 ;
    ANTENNADIFFAREA 0.434700 ;
    PORT
      LAYER met2 ;
        RECT 127.050 255.330 127.330 255.610 ;
    END
  END s_axi_araddr_10
  PIN s_axi_araddr_11
    DIRECTION INPUT ;
    USE SIGNAL ;
    ANTENNAGATEAREA 0.647700 ;
    ANTENNADIFFAREA 0.434700 ;
    PORT
      LAYER met2 ;
        RECT 114.170 255.330 114.450 255.610 ;
    END
  END s_axi_araddr_11
  PIN s_axi_araddr_12
    DIRECTION INPUT ;
    USE SIGNAL ;
    ANTENNAGATEAREA 0.647700 ;
    ANTENNADIFFAREA 0.434700 ;
    PORT
      LAYER met3 ;
        RECT 244.290 194.520 244.890 195.120 ;
    END
  END s_axi_araddr_12
  PIN s_axi_araddr_13
    DIRECTION INPUT ;
    USE SIGNAL ;
    ANTENNAGATEAREA 0.647700 ;
    ANTENNADIFFAREA 0.434700 ;
    PORT
      LAYER met2 ;
        RECT 189.610 255.330 189.890 255.610 ;
    END
  END s_axi_araddr_13
  PIN s_axi_araddr_14
    DIRECTION INPUT ;
    USE SIGNAL ;
    ANTENNAGATEAREA 0.647700 ;
    ANTENNADIFFAREA 0.434700 ;
    PORT
      LAYER met2 ;
        RECT 169.370 255.330 169.650 255.610 ;
    END
  END s_axi_araddr_14
  PIN s_axi_araddr_15
    DIRECTION INPUT ;
    USE SIGNAL ;
    ANTENNAGATEAREA 0.647700 ;
    ANTENNADIFFAREA 0.434700 ;
    PORT
      LAYER met2 ;
        RECT 156.490 255.330 156.770 255.610 ;
    END
  END s_axi_araddr_15
  PIN s_axi_araddr_16
    DIRECTION INPUT ;
    USE SIGNAL ;
    ANTENNAGATEAREA 0.647700 ;
    ANTENNADIFFAREA 0.434700 ;
    PORT
      LAYER met3 ;
        RECT 244.290 137.400 244.890 138.000 ;
    END
  END s_axi_araddr_16
  PIN s_axi_araddr_17
    DIRECTION INPUT ;
    USE SIGNAL ;
    ANTENNAGATEAREA 0.647700 ;
    ANTENNADIFFAREA 0.434700 ;
    PORT
      LAYER met3 ;
        RECT 244.290 145.560 244.890 146.160 ;
    END
  END s_axi_araddr_17
  PIN s_axi_araddr_18
    DIRECTION INPUT ;
    USE SIGNAL ;
    ANTENNAGATEAREA 0.647700 ;
    ANTENNADIFFAREA 0.434700 ;
    PORT
      LAYER met2 ;
        RECT 165.690 255.330 165.970 255.610 ;
    END
  END s_axi_araddr_18
  PIN s_axi_araddr_19
    DIRECTION INPUT ;
    USE SIGNAL ;
    ANTENNAGATEAREA 0.647700 ;
    ANTENNADIFFAREA 0.434700 ;
    PORT
      LAYER met3 ;
        RECT 244.290 122.440 244.890 123.040 ;
    END
  END s_axi_araddr_19
  PIN s_axi_araddr_2
    DIRECTION INPUT ;
    USE SIGNAL ;
    ANTENNAGATEAREA 0.647700 ;
    ANTENNADIFFAREA 0.434700 ;
    PORT
      LAYER met3 ;
        RECT 244.290 130.600 244.890 131.200 ;
    END
  END s_axi_araddr_2
  PIN s_axi_araddr_20
    DIRECTION INPUT ;
    USE SIGNAL ;
    ANTENNAGATEAREA 0.647700 ;
    ANTENNADIFFAREA 0.434700 ;
    PORT
      LAYER met3 ;
        RECT 0.000 115.640 0.600 116.240 ;
    END
  END s_axi_araddr_20
  PIN s_axi_araddr_21
    DIRECTION INPUT ;
    USE SIGNAL ;
    ANTENNAGATEAREA 0.647700 ;
    ANTENNADIFFAREA 0.434700 ;
    PORT
      LAYER met3 ;
        RECT 244.290 88.440 244.890 89.040 ;
    END
  END s_axi_araddr_21
  PIN s_axi_araddr_22
    DIRECTION INPUT ;
    USE SIGNAL ;
    ANTENNAGATEAREA 0.647700 ;
    ANTENNADIFFAREA 0.434700 ;
    PORT
      LAYER met2 ;
        RECT 141.770 0.000 142.050 0.280 ;
    END
  END s_axi_araddr_22
  PIN s_axi_araddr_23
    DIRECTION INPUT ;
    USE SIGNAL ;
    ANTENNAGATEAREA 0.647700 ;
    ANTENNADIFFAREA 0.434700 ;
    PORT
      LAYER met2 ;
        RECT 117.850 0.000 118.130 0.280 ;
    END
  END s_axi_araddr_23
  PIN s_axi_araddr_24
    DIRECTION INPUT ;
    USE SIGNAL ;
    ANTENNAGATEAREA 0.647700 ;
    ANTENNADIFFAREA 0.434700 ;
    PORT
      LAYER met2 ;
        RECT 211.690 0.000 211.970 0.280 ;
    END
  END s_axi_araddr_24
  PIN s_axi_araddr_25
    DIRECTION INPUT ;
    USE SIGNAL ;
    ANTENNAGATEAREA 0.647700 ;
    ANTENNADIFFAREA 0.434700 ;
    PORT
      LAYER met3 ;
        RECT 244.290 84.360 244.890 84.960 ;
    END
  END s_axi_araddr_25
  PIN s_axi_araddr_26
    DIRECTION INPUT ;
    USE SIGNAL ;
    ANTENNAGATEAREA 0.647700 ;
    ANTENNADIFFAREA 0.434700 ;
    PORT
      LAYER met2 ;
        RECT 108.650 0.000 108.930 0.280 ;
    END
  END s_axi_araddr_26
  PIN s_axi_araddr_27
    DIRECTION INPUT ;
    USE SIGNAL ;
    ANTENNAGATEAREA 0.647700 ;
    ANTENNADIFFAREA 0.434700 ;
    PORT
      LAYER met2 ;
        RECT 104.970 0.000 105.250 0.280 ;
    END
  END s_axi_araddr_27
  PIN s_axi_araddr_28
    DIRECTION INPUT ;
    USE SIGNAL ;
    ANTENNAGATEAREA 0.647700 ;
    ANTENNADIFFAREA 0.434700 ;
    PORT
      LAYER met2 ;
        RECT 221.810 0.000 222.090 0.280 ;
    END
  END s_axi_araddr_28
  PIN s_axi_araddr_29
    DIRECTION INPUT ;
    USE SIGNAL ;
    ANTENNAGATEAREA 0.647700 ;
    ANTENNADIFFAREA 0.434700 ;
    PORT
      LAYER met3 ;
        RECT 244.290 99.320 244.890 99.920 ;
    END
  END s_axi_araddr_29
  PIN s_axi_araddr_3
    DIRECTION INPUT ;
    USE SIGNAL ;
    ANTENNAGATEAREA 0.647700 ;
    ANTENNADIFFAREA 0.434700 ;
    PORT
      LAYER met3 ;
        RECT 244.290 118.360 244.890 118.960 ;
    END
  END s_axi_araddr_3
  PIN s_axi_araddr_30
    DIRECTION INPUT ;
    USE SIGNAL ;
    ANTENNAGATEAREA 0.647700 ;
    ANTENNADIFFAREA 0.434700 ;
    PORT
      LAYER met3 ;
        RECT 244.290 96.600 244.890 97.200 ;
    END
  END s_axi_araddr_30
  PIN s_axi_araddr_31
    DIRECTION INPUT ;
    USE SIGNAL ;
    ANTENNAGATEAREA 0.647700 ;
    ANTENNADIFFAREA 0.434700 ;
    PORT
      LAYER met3 ;
        RECT 0.000 133.320 0.600 133.920 ;
    END
  END s_axi_araddr_31
  PIN s_axi_araddr_4
    DIRECTION INPUT ;
    USE SIGNAL ;
    ANTENNAGATEAREA 0.647700 ;
    ANTENNADIFFAREA 0.434700 ;
    PORT
      LAYER met3 ;
        RECT 244.290 112.920 244.890 113.520 ;
    END
  END s_axi_araddr_4
  PIN s_axi_araddr_5
    DIRECTION INPUT ;
    USE SIGNAL ;
    ANTENNAGATEAREA 0.647700 ;
    ANTENNADIFFAREA 0.434700 ;
    PORT
      LAYER met3 ;
        RECT 244.290 160.520 244.890 161.120 ;
    END
  END s_axi_araddr_5
  PIN s_axi_araddr_6
    DIRECTION INPUT ;
    USE SIGNAL ;
    ANTENNAGATEAREA 0.647700 ;
    ANTENNADIFFAREA 0.434700 ;
    PORT
      LAYER met2 ;
        RECT 106.810 255.330 107.090 255.610 ;
    END
  END s_axi_araddr_6
  PIN s_axi_araddr_7
    DIRECTION INPUT ;
    USE SIGNAL ;
    ANTENNAGATEAREA 0.647700 ;
    ANTENNADIFFAREA 0.434700 ;
    PORT
      LAYER met2 ;
        RECT 108.650 255.330 108.930 255.610 ;
    END
  END s_axi_araddr_7
  PIN s_axi_araddr_8
    DIRECTION INPUT ;
    USE SIGNAL ;
    ANTENNAGATEAREA 0.647700 ;
    ANTENNADIFFAREA 0.434700 ;
    PORT
      LAYER met3 ;
        RECT 244.290 141.480 244.890 142.080 ;
    END
  END s_axi_araddr_8
  PIN s_axi_araddr_9
    DIRECTION INPUT ;
    USE SIGNAL ;
    ANTENNAGATEAREA 0.647700 ;
    ANTENNADIFFAREA 0.434700 ;
    PORT
      LAYER met2 ;
        RECT 141.770 255.330 142.050 255.610 ;
    END
  END s_axi_araddr_9
  PIN s_axi_arready
    DIRECTION OUTPUT ;
    USE SIGNAL ;
    ANTENNAGATEAREA 0.434700 ;
    ANTENNADIFFAREA 1.133700 ;
    PORT
      LAYER met3 ;
        RECT 0.000 151.000 0.600 151.600 ;
    END
  END s_axi_arready
  PIN s_axi_arvalid
    DIRECTION INPUT ;
    USE SIGNAL ;
    PORT
      LAYER met2 ;
        RECT 1.930 0.000 2.210 0.280 ;
    END
  END s_axi_arvalid
  PIN s_axi_awaddr_0
    DIRECTION INPUT ;
    USE SIGNAL ;
    ANTENNAGATEAREA 0.647700 ;
    ANTENNADIFFAREA 0.434700 ;
    PORT
      LAYER met2 ;
        RECT 137.170 255.330 137.450 255.610 ;
    END
  END s_axi_awaddr_0
  PIN s_axi_awaddr_1
    DIRECTION INPUT ;
    USE SIGNAL ;
    ANTENNAGATEAREA 0.647700 ;
    ANTENNADIFFAREA 0.434700 ;
    PORT
      LAYER met3 ;
        RECT 244.290 172.760 244.890 173.360 ;
    END
  END s_axi_awaddr_1
  PIN s_axi_awaddr_10
    DIRECTION INPUT ;
    USE SIGNAL ;
    ANTENNAGATEAREA 0.647700 ;
    ANTENNADIFFAREA 0.434700 ;
    PORT
      LAYER met2 ;
        RECT 126.130 255.330 126.410 255.610 ;
    END
  END s_axi_awaddr_10
  PIN s_axi_awaddr_11
    DIRECTION INPUT ;
    USE SIGNAL ;
    ANTENNAGATEAREA 0.647700 ;
    ANTENNADIFFAREA 0.434700 ;
    PORT
      LAYER met2 ;
        RECT 113.250 255.330 113.530 255.610 ;
    END
  END s_axi_awaddr_11
  PIN s_axi_awaddr_12
    DIRECTION INPUT ;
    USE SIGNAL ;
    ANTENNAGATEAREA 0.647700 ;
    ANTENNADIFFAREA 0.434700 ;
    PORT
      LAYER met3 ;
        RECT 244.290 195.880 244.890 196.480 ;
    END
  END s_axi_awaddr_12
  PIN s_axi_awaddr_13
    DIRECTION INPUT ;
    USE SIGNAL ;
    ANTENNAGATEAREA 0.647700 ;
    ANTENNADIFFAREA 0.434700 ;
    PORT
      LAYER met2 ;
        RECT 187.770 255.330 188.050 255.610 ;
    END
  END s_axi_awaddr_13
  PIN s_axi_awaddr_14
    DIRECTION INPUT ;
    USE SIGNAL ;
    ANTENNAGATEAREA 0.647700 ;
    ANTENNADIFFAREA 0.434700 ;
    PORT
      LAYER met2 ;
        RECT 167.530 255.330 167.810 255.610 ;
    END
  END s_axi_awaddr_14
  PIN s_axi_awaddr_15
    DIRECTION INPUT ;
    USE SIGNAL ;
    ANTENNAGATEAREA 0.647700 ;
    ANTENNADIFFAREA 0.434700 ;
    PORT
      LAYER met2 ;
        RECT 154.650 255.330 154.930 255.610 ;
    END
  END s_axi_awaddr_15
  PIN s_axi_awaddr_16
    DIRECTION INPUT ;
    USE SIGNAL ;
    ANTENNAGATEAREA 0.647700 ;
    ANTENNADIFFAREA 0.434700 ;
    PORT
      LAYER met3 ;
        RECT 244.290 136.040 244.890 136.640 ;
    END
  END s_axi_awaddr_16
  PIN s_axi_awaddr_17
    DIRECTION INPUT ;
    USE SIGNAL ;
    ANTENNAGATEAREA 0.647700 ;
    ANTENNADIFFAREA 0.434700 ;
    PORT
      LAYER met3 ;
        RECT 244.290 142.840 244.890 143.440 ;
    END
  END s_axi_awaddr_17
  PIN s_axi_awaddr_18
    DIRECTION INPUT ;
    USE SIGNAL ;
    ANTENNAGATEAREA 0.647700 ;
    ANTENNADIFFAREA 0.434700 ;
    PORT
      LAYER met2 ;
        RECT 162.930 255.330 163.210 255.610 ;
    END
  END s_axi_awaddr_18
  PIN s_axi_awaddr_19
    DIRECTION INPUT ;
    USE SIGNAL ;
    ANTENNAGATEAREA 0.647700 ;
    ANTENNADIFFAREA 0.434700 ;
    PORT
      LAYER met3 ;
        RECT 244.290 121.080 244.890 121.680 ;
    END
  END s_axi_awaddr_19
  PIN s_axi_awaddr_2
    DIRECTION INPUT ;
    USE SIGNAL ;
    ANTENNAGATEAREA 0.647700 ;
    ANTENNADIFFAREA 0.434700 ;
    PORT
      LAYER met3 ;
        RECT 244.290 131.960 244.890 132.560 ;
    END
  END s_axi_awaddr_2
  PIN s_axi_awaddr_20
    DIRECTION INPUT ;
    USE SIGNAL ;
    ANTENNAGATEAREA 0.647700 ;
    ANTENNADIFFAREA 0.434700 ;
    PORT
      LAYER met3 ;
        RECT 0.000 114.280 0.600 114.880 ;
    END
  END s_axi_awaddr_20
  PIN s_axi_awaddr_21
    DIRECTION INPUT ;
    USE SIGNAL ;
    ANTENNAGATEAREA 0.647700 ;
    ANTENNADIFFAREA 0.434700 ;
    PORT
      LAYER met3 ;
        RECT 244.290 89.800 244.890 90.400 ;
    END
  END s_axi_awaddr_21
  PIN s_axi_awaddr_22
    DIRECTION INPUT ;
    USE SIGNAL ;
    ANTENNAGATEAREA 0.647700 ;
    ANTENNADIFFAREA 0.434700 ;
    PORT
      LAYER met2 ;
        RECT 139.010 0.000 139.290 0.280 ;
    END
  END s_axi_awaddr_22
  PIN s_axi_awaddr_23
    DIRECTION INPUT ;
    USE SIGNAL ;
    ANTENNAGATEAREA 0.647700 ;
    ANTENNADIFFAREA 0.434700 ;
    PORT
      LAYER met2 ;
        RECT 116.930 0.000 117.210 0.280 ;
    END
  END s_axi_awaddr_23
  PIN s_axi_awaddr_24
    DIRECTION INPUT ;
    USE SIGNAL ;
    ANTENNAGATEAREA 0.647700 ;
    ANTENNADIFFAREA 0.434700 ;
    PORT
      LAYER met2 ;
        RECT 191.450 0.000 191.730 0.280 ;
    END
  END s_axi_awaddr_24
  PIN s_axi_awaddr_25
    DIRECTION INPUT ;
    USE SIGNAL ;
    ANTENNAGATEAREA 0.647700 ;
    ANTENNADIFFAREA 0.434700 ;
    PORT
      LAYER met3 ;
        RECT 244.290 85.720 244.890 86.320 ;
    END
  END s_axi_awaddr_25
  PIN s_axi_awaddr_26
    DIRECTION INPUT ;
    USE SIGNAL ;
    ANTENNAGATEAREA 0.647700 ;
    ANTENNADIFFAREA 0.434700 ;
    PORT
      LAYER met2 ;
        RECT 106.810 0.000 107.090 0.280 ;
    END
  END s_axi_awaddr_26
  PIN s_axi_awaddr_27
    DIRECTION INPUT ;
    USE SIGNAL ;
    ANTENNAGATEAREA 0.647700 ;
    ANTENNADIFFAREA 0.434700 ;
    PORT
      LAYER met2 ;
        RECT 104.050 0.000 104.330 0.280 ;
    END
  END s_axi_awaddr_27
  PIN s_axi_awaddr_28
    DIRECTION INPUT ;
    USE SIGNAL ;
    ANTENNAGATEAREA 0.647700 ;
    ANTENNADIFFAREA 0.434700 ;
    PORT
      LAYER met2 ;
        RECT 219.050 0.000 219.330 0.280 ;
    END
  END s_axi_awaddr_28
  PIN s_axi_awaddr_29
    DIRECTION INPUT ;
    USE SIGNAL ;
    ANTENNAGATEAREA 0.647700 ;
    ANTENNADIFFAREA 0.434700 ;
    PORT
      LAYER met3 ;
        RECT 244.290 97.960 244.890 98.560 ;
    END
  END s_axi_awaddr_29
  PIN s_axi_awaddr_3
    DIRECTION INPUT ;
    USE SIGNAL ;
    ANTENNAGATEAREA 0.647700 ;
    ANTENNADIFFAREA 0.434700 ;
    PORT
      LAYER met3 ;
        RECT 244.290 117.000 244.890 117.600 ;
    END
  END s_axi_awaddr_3
  PIN s_axi_awaddr_30
    DIRECTION INPUT ;
    USE SIGNAL ;
    ANTENNAGATEAREA 0.647700 ;
    ANTENNADIFFAREA 0.434700 ;
    PORT
      LAYER met3 ;
        RECT 244.290 93.880 244.890 94.480 ;
    END
  END s_axi_awaddr_30
  PIN s_axi_awaddr_31
    DIRECTION INPUT ;
    USE SIGNAL ;
    ANTENNAGATEAREA 0.647700 ;
    ANTENNADIFFAREA 0.434700 ;
    PORT
      LAYER met3 ;
        RECT 0.000 136.040 0.600 136.640 ;
    END
  END s_axi_awaddr_31
  PIN s_axi_awaddr_4
    DIRECTION INPUT ;
    USE SIGNAL ;
    ANTENNAGATEAREA 0.647700 ;
    ANTENNADIFFAREA 0.434700 ;
    PORT
      LAYER met3 ;
        RECT 244.290 111.560 244.890 112.160 ;
    END
  END s_axi_awaddr_4
  PIN s_axi_awaddr_5
    DIRECTION INPUT ;
    USE SIGNAL ;
    ANTENNAGATEAREA 0.647700 ;
    ANTENNADIFFAREA 0.434700 ;
    PORT
      LAYER met3 ;
        RECT 244.290 161.880 244.890 162.480 ;
    END
  END s_axi_awaddr_5
  PIN s_axi_awaddr_6
    DIRECTION INPUT ;
    USE SIGNAL ;
    ANTENNAGATEAREA 0.647700 ;
    ANTENNADIFFAREA 0.434700 ;
    PORT
      LAYER met2 ;
        RECT 104.970 255.330 105.250 255.610 ;
    END
  END s_axi_awaddr_6
  PIN s_axi_awaddr_7
    DIRECTION INPUT ;
    USE SIGNAL ;
    ANTENNAGATEAREA 0.647700 ;
    ANTENNADIFFAREA 0.434700 ;
    PORT
      LAYER met2 ;
        RECT 107.730 255.330 108.010 255.610 ;
    END
  END s_axi_awaddr_7
  PIN s_axi_awaddr_8
    DIRECTION INPUT ;
    USE SIGNAL ;
    ANTENNAGATEAREA 0.647700 ;
    ANTENNADIFFAREA 0.434700 ;
    PORT
      LAYER met3 ;
        RECT 244.290 144.200 244.890 144.800 ;
    END
  END s_axi_awaddr_8
  PIN s_axi_awaddr_9
    DIRECTION INPUT ;
    USE SIGNAL ;
    ANTENNAGATEAREA 0.647700 ;
    ANTENNADIFFAREA 0.434700 ;
    PORT
      LAYER met2 ;
        RECT 140.850 255.330 141.130 255.610 ;
    END
  END s_axi_awaddr_9
  PIN s_axi_awready
    DIRECTION OUTPUT ;
    USE SIGNAL ;
    ANTENNAGATEAREA 0.434700 ;
    ANTENNADIFFAREA 0.832300 ;
    PORT
      LAYER met3 ;
        RECT 0.000 221.720 0.600 222.320 ;
    END
  END s_axi_awready
  PIN s_axi_awvalid
    DIRECTION INPUT ;
    USE SIGNAL ;
    ANTENNAGATEAREA 0.647700 ;
    ANTENNADIFFAREA 0.434700 ;
    PORT
      LAYER met3 ;
        RECT 244.290 170.040 244.890 170.640 ;
    END
  END s_axi_awvalid
  PIN s_axi_bready
    DIRECTION INPUT ;
    USE SIGNAL ;
    PORT
      LAYER met2 ;
        RECT 2.850 0.000 3.130 0.280 ;
    END
  END s_axi_bready
  PIN s_axi_bresp_0
    DIRECTION OUTPUT ;
    USE SIGNAL ;
    ANTENNAGATEAREA 0.434700 ;
    ANTENNADIFFAREA 0.434700 ;
    PORT
      LAYER met3 ;
        RECT 244.290 197.240 244.890 197.840 ;
    END
  END s_axi_bresp_0
  PIN s_axi_bresp_1
    DIRECTION OUTPUT ;
    USE SIGNAL ;
    ANTENNAGATEAREA 0.434700 ;
    ANTENNADIFFAREA 1.137600 ;
    PORT
      LAYER met2 ;
        RECT 214.450 0.000 214.730 0.280 ;
    END
  END s_axi_bresp_1
  PIN s_axi_bvalid
    DIRECTION OUTPUT ;
    USE SIGNAL ;
    ANTENNAGATEAREA 0.434700 ;
    ANTENNADIFFAREA 0.775300 ;
    PORT
      LAYER met3 ;
        RECT 244.290 202.680 244.890 203.280 ;
    END
  END s_axi_bvalid
  PIN s_axi_rdata_0
    DIRECTION OUTPUT ;
    USE SIGNAL ;
    ANTENNAGATEAREA 0.434700 ;
    ANTENNADIFFAREA 1.137600 ;
    PORT
      LAYER met2 ;
        RECT 209.850 0.000 210.130 0.280 ;
    END
  END s_axi_rdata_0
  PIN s_axi_rdata_1
    DIRECTION OUTPUT ;
    USE SIGNAL ;
    ANTENNAGATEAREA 0.434700 ;
    ANTENNADIFFAREA 1.137600 ;
    PORT
      LAYER met2 ;
        RECT 190.530 0.000 190.810 0.280 ;
    END
  END s_axi_rdata_1
  PIN s_axi_rdata_10
    DIRECTION OUTPUT ;
    USE SIGNAL ;
    ANTENNAGATEAREA 0.434700 ;
    ANTENNADIFFAREA 1.137600 ;
    PORT
      LAYER met2 ;
        RECT 130.730 0.000 131.010 0.280 ;
    END
  END s_axi_rdata_10
  PIN s_axi_rdata_11
    DIRECTION OUTPUT ;
    USE SIGNAL ;
    ANTENNAGATEAREA 0.434700 ;
    ANTENNADIFFAREA 1.137600 ;
    PORT
      LAYER met2 ;
        RECT 125.210 0.000 125.490 0.280 ;
    END
  END s_axi_rdata_11
  PIN s_axi_rdata_12
    DIRECTION OUTPUT ;
    USE SIGNAL ;
    ANTENNAGATEAREA 0.434700 ;
    ANTENNADIFFAREA 1.137600 ;
    PORT
      LAYER met2 ;
        RECT 213.530 0.000 213.810 0.280 ;
    END
  END s_axi_rdata_12
  PIN s_axi_rdata_13
    DIRECTION OUTPUT ;
    USE SIGNAL ;
    ANTENNAGATEAREA 0.434700 ;
    ANTENNADIFFAREA 1.137600 ;
    PORT
      LAYER met2 ;
        RECT 126.130 0.000 126.410 0.280 ;
    END
  END s_axi_rdata_13
  PIN s_axi_rdata_14
    DIRECTION OUTPUT ;
    USE SIGNAL ;
    ANTENNAGATEAREA 0.434700 ;
    ANTENNADIFFAREA 1.137600 ;
    PORT
      LAYER met2 ;
        RECT 128.890 0.000 129.170 0.280 ;
    END
  END s_axi_rdata_14
  PIN s_axi_rdata_15
    DIRECTION OUTPUT ;
    USE SIGNAL ;
    ANTENNAGATEAREA 0.434700 ;
    ANTENNADIFFAREA 1.137600 ;
    PORT
      LAYER met2 ;
        RECT 201.570 0.000 201.850 0.280 ;
    END
  END s_axi_rdata_15
  PIN s_axi_rdata_16
    DIRECTION OUTPUT ;
    USE SIGNAL ;
    ANTENNAGATEAREA 0.434700 ;
    ANTENNADIFFAREA 1.137600 ;
    PORT
      LAYER met2 ;
        RECT 222.730 0.000 223.010 0.280 ;
    END
  END s_axi_rdata_16
  PIN s_axi_rdata_17
    DIRECTION OUTPUT ;
    USE SIGNAL ;
    ANTENNAGATEAREA 0.434700 ;
    ANTENNADIFFAREA 1.137600 ;
    PORT
      LAYER met2 ;
        RECT 129.810 0.000 130.090 0.280 ;
    END
  END s_axi_rdata_17
  PIN s_axi_rdata_18
    DIRECTION OUTPUT ;
    USE SIGNAL ;
    ANTENNAGATEAREA 0.434700 ;
    ANTENNADIFFAREA 1.137600 ;
    PORT
      LAYER met2 ;
        RECT 208.010 0.000 208.290 0.280 ;
    END
  END s_axi_rdata_18
  PIN s_axi_rdata_19
    DIRECTION OUTPUT ;
    USE SIGNAL ;
    ANTENNAGATEAREA 0.434700 ;
    ANTENNADIFFAREA 1.137600 ;
    PORT
      LAYER met2 ;
        RECT 186.850 0.000 187.130 0.280 ;
    END
  END s_axi_rdata_19
  PIN s_axi_rdata_2
    DIRECTION OUTPUT ;
    USE SIGNAL ;
    ANTENNAGATEAREA 0.434700 ;
    ANTENNADIFFAREA 1.137600 ;
    PORT
      LAYER met2 ;
        RECT 121.530 0.000 121.810 0.280 ;
    END
  END s_axi_rdata_2
  PIN s_axi_rdata_20
    DIRECTION OUTPUT ;
    USE SIGNAL ;
    ANTENNAGATEAREA 0.434700 ;
    ANTENNADIFFAREA 1.137600 ;
    PORT
      LAYER met2 ;
        RECT 151.890 0.000 152.170 0.280 ;
    END
  END s_axi_rdata_20
  PIN s_axi_rdata_21
    DIRECTION OUTPUT ;
    USE SIGNAL ;
    ANTENNAGATEAREA 0.434700 ;
    ANTENNADIFFAREA 1.137600 ;
    PORT
      LAYER met2 ;
        RECT 215.370 0.000 215.650 0.280 ;
    END
  END s_axi_rdata_21
  PIN s_axi_rdata_22
    DIRECTION OUTPUT ;
    USE SIGNAL ;
    ANTENNAGATEAREA 0.434700 ;
    ANTENNADIFFAREA 1.137600 ;
    PORT
      LAYER met2 ;
        RECT 195.130 0.000 195.410 0.280 ;
    END
  END s_axi_rdata_22
  PIN s_axi_rdata_23
    DIRECTION OUTPUT ;
    USE SIGNAL ;
    ANTENNAGATEAREA 0.434700 ;
    ANTENNADIFFAREA 1.137600 ;
    PORT
      LAYER met2 ;
        RECT 188.690 0.000 188.970 0.280 ;
    END
  END s_axi_rdata_23
  PIN s_axi_rdata_24
    DIRECTION OUTPUT ;
    USE SIGNAL ;
    ANTENNAGATEAREA 0.434700 ;
    ANTENNADIFFAREA 1.137600 ;
    PORT
      LAYER met2 ;
        RECT 216.290 0.000 216.570 0.280 ;
    END
  END s_axi_rdata_24
  PIN s_axi_rdata_25
    DIRECTION OUTPUT ;
    USE SIGNAL ;
    ANTENNAGATEAREA 0.434700 ;
    ANTENNADIFFAREA 1.137600 ;
    PORT
      LAYER met2 ;
        RECT 192.370 0.000 192.650 0.280 ;
    END
  END s_axi_rdata_25
  PIN s_axi_rdata_26
    DIRECTION OUTPUT ;
    USE SIGNAL ;
    ANTENNAGATEAREA 0.434700 ;
    ANTENNADIFFAREA 1.137600 ;
    PORT
      LAYER met2 ;
        RECT 134.410 0.000 134.690 0.280 ;
    END
  END s_axi_rdata_26
  PIN s_axi_rdata_27
    DIRECTION OUTPUT ;
    USE SIGNAL ;
    ANTENNAGATEAREA 0.434700 ;
    ANTENNADIFFAREA 1.137600 ;
    PORT
      LAYER met2 ;
        RECT 120.610 0.000 120.890 0.280 ;
    END
  END s_axi_rdata_27
  PIN s_axi_rdata_28
    DIRECTION OUTPUT ;
    USE SIGNAL ;
    ANTENNAGATEAREA 0.434700 ;
    ANTENNADIFFAREA 1.137600 ;
    PORT
      LAYER met2 ;
        RECT 218.130 0.000 218.410 0.280 ;
    END
  END s_axi_rdata_28
  PIN s_axi_rdata_29
    DIRECTION OUTPUT ;
    USE SIGNAL ;
    ANTENNAGATEAREA 0.434700 ;
    ANTENNADIFFAREA 1.137600 ;
    PORT
      LAYER met2 ;
        RECT 223.650 0.000 223.930 0.280 ;
    END
  END s_axi_rdata_29
  PIN s_axi_rdata_3
    DIRECTION OUTPUT ;
    USE SIGNAL ;
    ANTENNAGATEAREA 0.434700 ;
    ANTENNADIFFAREA 1.137600 ;
    PORT
      LAYER met2 ;
        RECT 138.090 0.000 138.370 0.280 ;
    END
  END s_axi_rdata_3
  PIN s_axi_rdata_30
    DIRECTION OUTPUT ;
    USE SIGNAL ;
    ANTENNAGATEAREA 0.434700 ;
    ANTENNADIFFAREA 1.137600 ;
    PORT
      LAYER met2 ;
        RECT 153.730 0.000 154.010 0.280 ;
    END
  END s_axi_rdata_30
  PIN s_axi_rdata_31
    DIRECTION OUTPUT ;
    USE SIGNAL ;
    ANTENNAGATEAREA 0.434700 ;
    ANTENNADIFFAREA 1.137600 ;
    PORT
      LAYER met2 ;
        RECT 200.650 0.000 200.930 0.280 ;
    END
  END s_axi_rdata_31
  PIN s_axi_rdata_4
    DIRECTION OUTPUT ;
    USE SIGNAL ;
    ANTENNAGATEAREA 0.434700 ;
    ANTENNADIFFAREA 1.137600 ;
    PORT
      LAYER met2 ;
        RECT 148.210 0.000 148.490 0.280 ;
    END
  END s_axi_rdata_4
  PIN s_axi_rdata_5
    DIRECTION OUTPUT ;
    USE SIGNAL ;
    ANTENNAGATEAREA 0.434700 ;
    ANTENNADIFFAREA 1.137600 ;
    PORT
      LAYER met2 ;
        RECT 207.090 0.000 207.370 0.280 ;
    END
  END s_axi_rdata_5
  PIN s_axi_rdata_6
    DIRECTION OUTPUT ;
    USE SIGNAL ;
    ANTENNAGATEAREA 0.434700 ;
    ANTENNADIFFAREA 1.137600 ;
    PORT
      LAYER met2 ;
        RECT 217.210 0.000 217.490 0.280 ;
    END
  END s_axi_rdata_6
  PIN s_axi_rdata_7
    DIRECTION OUTPUT ;
    USE SIGNAL ;
    ANTENNAGATEAREA 0.434700 ;
    ANTENNADIFFAREA 1.137600 ;
    PORT
      LAYER met2 ;
        RECT 193.290 0.000 193.570 0.280 ;
    END
  END s_axi_rdata_7
  PIN s_axi_rdata_8
    DIRECTION OUTPUT ;
    USE SIGNAL ;
    ANTENNAGATEAREA 0.434700 ;
    ANTENNADIFFAREA 1.137600 ;
    PORT
      LAYER met2 ;
        RECT 152.810 0.000 153.090 0.280 ;
    END
  END s_axi_rdata_8
  PIN s_axi_rdata_9
    DIRECTION OUTPUT ;
    USE SIGNAL ;
    ANTENNAGATEAREA 0.434700 ;
    ANTENNADIFFAREA 1.137600 ;
    PORT
      LAYER met2 ;
        RECT 150.050 0.000 150.330 0.280 ;
    END
  END s_axi_rdata_9
  PIN s_axi_rready
    DIRECTION INPUT ;
    USE SIGNAL ;
    PORT
      LAYER met2 ;
        RECT 3.770 0.000 4.050 0.280 ;
    END
  END s_axi_rready
  PIN s_axi_rresp_0
    DIRECTION OUTPUT ;
    USE SIGNAL ;
    ANTENNAGATEAREA 0.434700 ;
    ANTENNADIFFAREA 0.775300 ;
    PORT
      LAYER met3 ;
        RECT 244.290 201.320 244.890 201.920 ;
    END
  END s_axi_rresp_0
  PIN s_axi_rresp_1
    DIRECTION OUTPUT ;
    USE SIGNAL ;
    ANTENNAGATEAREA 0.434700 ;
    ANTENNADIFFAREA 1.137600 ;
    PORT
      LAYER met2 ;
        RECT 212.610 0.000 212.890 0.280 ;
    END
  END s_axi_rresp_1
  PIN s_axi_rvalid
    DIRECTION OUTPUT ;
    USE SIGNAL ;
    ANTENNAGATEAREA 0.434700 ;
    ANTENNADIFFAREA 0.775300 ;
    PORT
      LAYER met3 ;
        RECT 244.290 199.960 244.890 200.560 ;
    END
  END s_axi_rvalid
  PIN s_axi_wdata_0
    DIRECTION INPUT ;
    USE SIGNAL ;
    ANTENNAGATEAREA 0.647700 ;
    ANTENNADIFFAREA 0.434700 ;
    PORT
      LAYER met3 ;
        RECT 0.000 111.560 0.600 112.160 ;
    END
  END s_axi_wdata_0
  PIN s_axi_wdata_1
    DIRECTION INPUT ;
    USE SIGNAL ;
    ANTENNAGATEAREA 0.647700 ;
    ANTENNADIFFAREA 0.434700 ;
    PORT
      LAYER met3 ;
        RECT 0.000 47.640 0.600 48.240 ;
    END
  END s_axi_wdata_1
  PIN s_axi_wdata_10
    DIRECTION INPUT ;
    USE SIGNAL ;
    ANTENNAGATEAREA 0.647700 ;
    ANTENNADIFFAREA 0.434700 ;
    PORT
      LAYER met3 ;
        RECT 0.000 167.320 0.600 167.920 ;
    END
  END s_axi_wdata_10
  PIN s_axi_wdata_11
    DIRECTION INPUT ;
    USE SIGNAL ;
    ANTENNAGATEAREA 0.647700 ;
    ANTENNADIFFAREA 0.434700 ;
    PORT
      LAYER met2 ;
        RECT 47.930 0.000 48.210 0.280 ;
    END
  END s_axi_wdata_11
  PIN s_axi_wdata_12
    DIRECTION INPUT ;
    USE SIGNAL ;
    ANTENNAGATEAREA 0.647700 ;
    ANTENNADIFFAREA 0.434700 ;
    PORT
      LAYER met3 ;
        RECT 0.000 97.960 0.600 98.560 ;
    END
  END s_axi_wdata_12
  PIN s_axi_wdata_13
    DIRECTION INPUT ;
    USE SIGNAL ;
    ANTENNAGATEAREA 0.647700 ;
    ANTENNADIFFAREA 0.434700 ;
    PORT
      LAYER met3 ;
        RECT 0.000 92.520 0.600 93.120 ;
    END
  END s_axi_wdata_13
  PIN s_axi_wdata_14
    DIRECTION INPUT ;
    USE SIGNAL ;
    ANTENNAGATEAREA 0.647700 ;
    ANTENNADIFFAREA 0.434700 ;
    PORT
      LAYER met2 ;
        RECT 35.970 0.000 36.250 0.280 ;
    END
  END s_axi_wdata_14
  PIN s_axi_wdata_15
    DIRECTION INPUT ;
    USE SIGNAL ;
    ANTENNAGATEAREA 0.647700 ;
    ANTENNADIFFAREA 0.434700 ;
    PORT
      LAYER met3 ;
        RECT 0.000 69.400 0.600 70.000 ;
    END
  END s_axi_wdata_15
  PIN s_axi_wdata_16
    DIRECTION INPUT ;
    USE SIGNAL ;
    ANTENNAGATEAREA 0.647700 ;
    ANTENNADIFFAREA 0.434700 ;
    PORT
      LAYER met3 ;
        RECT 0.000 144.200 0.600 144.800 ;
    END
  END s_axi_wdata_16
  PIN s_axi_wdata_17
    DIRECTION INPUT ;
    USE SIGNAL ;
    ANTENNAGATEAREA 0.647700 ;
    ANTENNADIFFAREA 0.434700 ;
    PORT
      LAYER met3 ;
        RECT 0.000 62.600 0.600 63.200 ;
    END
  END s_axi_wdata_17
  PIN s_axi_wdata_18
    DIRECTION INPUT ;
    USE SIGNAL ;
    ANTENNAGATEAREA 0.647700 ;
    ANTENNADIFFAREA 0.434700 ;
    PORT
      LAYER met3 ;
        RECT 0.000 110.200 0.600 110.800 ;
    END
  END s_axi_wdata_18
  PIN s_axi_wdata_19
    DIRECTION INPUT ;
    USE SIGNAL ;
    ANTENNAGATEAREA 0.647700 ;
    ANTENNADIFFAREA 0.434700 ;
    PORT
      LAYER met3 ;
        RECT 0.000 121.080 0.600 121.680 ;
    END
  END s_axi_wdata_19
  PIN s_axi_wdata_2
    DIRECTION INPUT ;
    USE SIGNAL ;
    ANTENNAGATEAREA 0.647700 ;
    ANTENNADIFFAREA 0.434700 ;
    PORT
      LAYER met2 ;
        RECT 91.170 255.330 91.450 255.610 ;
    END
  END s_axi_wdata_2
  PIN s_axi_wdata_20
    DIRECTION INPUT ;
    USE SIGNAL ;
    ANTENNAGATEAREA 0.647700 ;
    ANTENNADIFFAREA 0.434700 ;
    PORT
      LAYER met3 ;
        RECT 0.000 102.040 0.600 102.640 ;
    END
  END s_axi_wdata_20
  PIN s_axi_wdata_21
    DIRECTION INPUT ;
    USE SIGNAL ;
    ANTENNAGATEAREA 0.647700 ;
    ANTENNADIFFAREA 0.434700 ;
    PORT
      LAYER met2 ;
        RECT 24.930 255.330 25.210 255.610 ;
    END
  END s_axi_wdata_21
  PIN s_axi_wdata_22
    DIRECTION INPUT ;
    USE SIGNAL ;
    ANTENNAGATEAREA 0.647700 ;
    ANTENNADIFFAREA 0.434700 ;
    PORT
      LAYER met3 ;
        RECT 0.000 172.760 0.600 173.360 ;
    END
  END s_axi_wdata_22
  PIN s_axi_wdata_23
    DIRECTION INPUT ;
    USE SIGNAL ;
    ANTENNAGATEAREA 0.647700 ;
    ANTENNADIFFAREA 0.434700 ;
    PORT
      LAYER met2 ;
        RECT 23.090 255.330 23.370 255.610 ;
    END
  END s_axi_wdata_23
  PIN s_axi_wdata_24
    DIRECTION INPUT ;
    USE SIGNAL ;
    ANTENNAGATEAREA 0.647700 ;
    ANTENNADIFFAREA 0.434700 ;
    PORT
      LAYER met2 ;
        RECT 24.010 255.330 24.290 255.610 ;
    END
  END s_axi_wdata_24
  PIN s_axi_wdata_25
    DIRECTION INPUT ;
    USE SIGNAL ;
    ANTENNAGATEAREA 0.647700 ;
    ANTENNADIFFAREA 0.434700 ;
    PORT
      LAYER met2 ;
        RECT 57.130 255.330 57.410 255.610 ;
    END
  END s_axi_wdata_25
  PIN s_axi_wdata_26
    DIRECTION INPUT ;
    USE SIGNAL ;
    ANTENNAGATEAREA 0.647700 ;
    ANTENNADIFFAREA 0.434700 ;
    PORT
      LAYER met2 ;
        RECT 51.610 255.330 51.890 255.610 ;
    END
  END s_axi_wdata_26
  PIN s_axi_wdata_27
    DIRECTION INPUT ;
    USE SIGNAL ;
    ANTENNAGATEAREA 0.647700 ;
    ANTENNADIFFAREA 0.434700 ;
    PORT
      LAYER met2 ;
        RECT 53.450 255.330 53.730 255.610 ;
    END
  END s_axi_wdata_27
  PIN s_axi_wdata_28
    DIRECTION INPUT ;
    USE SIGNAL ;
    ANTENNAGATEAREA 0.647700 ;
    ANTENNADIFFAREA 0.434700 ;
    PORT
      LAYER met2 ;
        RECT 58.050 255.330 58.330 255.610 ;
    END
  END s_axi_wdata_28
  PIN s_axi_wdata_29
    DIRECTION INPUT ;
    USE SIGNAL ;
    ANTENNAGATEAREA 0.647700 ;
    ANTENNADIFFAREA 0.434700 ;
    PORT
      LAYER met2 ;
        RECT 48.850 255.330 49.130 255.610 ;
    END
  END s_axi_wdata_29
  PIN s_axi_wdata_3
    DIRECTION INPUT ;
    USE SIGNAL ;
    ANTENNAGATEAREA 0.647700 ;
    ANTENNADIFFAREA 0.434700 ;
    PORT
      LAYER met3 ;
        RECT 0.000 142.840 0.600 143.440 ;
    END
  END s_axi_wdata_3
  PIN s_axi_wdata_30
    DIRECTION INPUT ;
    USE SIGNAL ;
    ANTENNAGATEAREA 0.647700 ;
    ANTENNADIFFAREA 0.434700 ;
    PORT
      LAYER met2 ;
        RECT 52.530 255.330 52.810 255.610 ;
    END
  END s_axi_wdata_30
  PIN s_axi_wdata_31
    DIRECTION INPUT ;
    USE SIGNAL ;
    ANTENNAGATEAREA 0.647700 ;
    ANTENNADIFFAREA 0.434700 ;
    PORT
      LAYER met2 ;
        RECT 50.690 255.330 50.970 255.610 ;
    END
  END s_axi_wdata_31
  PIN s_axi_wdata_4
    DIRECTION INPUT ;
    USE SIGNAL ;
    ANTENNAGATEAREA 0.647700 ;
    ANTENNADIFFAREA 0.434700 ;
    PORT
      LAYER met2 ;
        RECT 92.090 0.000 92.370 0.280 ;
    END
  END s_axi_wdata_4
  PIN s_axi_wdata_5
    DIRECTION INPUT ;
    USE SIGNAL ;
    ANTENNAGATEAREA 0.647700 ;
    ANTENNADIFFAREA 0.434700 ;
    PORT
      LAYER met2 ;
        RECT 78.290 0.000 78.570 0.280 ;
    END
  END s_axi_wdata_5
  PIN s_axi_wdata_6
    DIRECTION INPUT ;
    USE SIGNAL ;
    ANTENNAGATEAREA 0.647700 ;
    ANTENNADIFFAREA 0.434700 ;
    PORT
      LAYER met2 ;
        RECT 69.090 0.000 69.370 0.280 ;
    END
  END s_axi_wdata_6
  PIN s_axi_wdata_7
    DIRECTION INPUT ;
    USE SIGNAL ;
    ANTENNAGATEAREA 0.647700 ;
    ANTENNADIFFAREA 0.434700 ;
    PORT
      LAYER met2 ;
        RECT 79.210 0.000 79.490 0.280 ;
    END
  END s_axi_wdata_7
  PIN s_axi_wdata_8
    DIRECTION INPUT ;
    USE SIGNAL ;
    ANTENNAGATEAREA 0.647700 ;
    ANTENNADIFFAREA 0.434700 ;
    PORT
      LAYER met3 ;
        RECT 0.000 78.920 0.600 79.520 ;
    END
  END s_axi_wdata_8
  PIN s_axi_wdata_9
    DIRECTION INPUT ;
    USE SIGNAL ;
    ANTENNAGATEAREA 0.647700 ;
    ANTENNADIFFAREA 0.434700 ;
    PORT
      LAYER met3 ;
        RECT 0.000 76.200 0.600 76.800 ;
    END
  END s_axi_wdata_9
  PIN s_axi_wready
    DIRECTION OUTPUT ;
    USE SIGNAL ;
    ANTENNAGATEAREA 0.434700 ;
    ANTENNADIFFAREA 0.832300 ;
    PORT
      LAYER met3 ;
        RECT 0.000 100.680 0.600 101.280 ;
    END
  END s_axi_wready
  PIN s_axi_wstrb_0
    DIRECTION INPUT ;
    USE SIGNAL ;
    ANTENNAGATEAREA 0.647700 ;
    ANTENNADIFFAREA 0.434700 ;
    PORT
      LAYER met3 ;
        RECT 0.000 130.600 0.600 131.200 ;
    END
  END s_axi_wstrb_0
  PIN s_axi_wstrb_1
    DIRECTION INPUT ;
    USE SIGNAL ;
    ANTENNAGATEAREA 0.647700 ;
    ANTENNADIFFAREA 0.434700 ;
    PORT
      LAYER met3 ;
        RECT 0.000 129.240 0.600 129.840 ;
    END
  END s_axi_wstrb_1
  PIN s_axi_wstrb_2
    DIRECTION INPUT ;
    USE SIGNAL ;
    ANTENNAGATEAREA 0.647700 ;
    ANTENNADIFFAREA 0.434700 ;
    PORT
      LAYER met3 ;
        RECT 0.000 159.160 0.600 159.760 ;
    END
  END s_axi_wstrb_2
  PIN s_axi_wstrb_3
    DIRECTION INPUT ;
    USE SIGNAL ;
    ANTENNAGATEAREA 0.647700 ;
    ANTENNADIFFAREA 0.434700 ;
    PORT
      LAYER met3 ;
        RECT 0.000 152.360 0.600 152.960 ;
    END
  END s_axi_wstrb_3
  PIN s_axi_wvalid
    DIRECTION INPUT ;
    USE SIGNAL ;
    ANTENNAGATEAREA 0.647700 ;
    ANTENNADIFFAREA 0.434700 ;
    PORT
      LAYER met3 ;
        RECT 244.290 168.680 244.890 169.280 ;
    END
  END s_axi_wvalid
  OBS
      LAYER nwell ;
        RECT 5.330 10.795 239.390 242.270 ;
      LAYER li1 ;
        RECT 5.520 10.795 239.200 242.165 ;
      LAYER met1 ;
        RECT 5.520 6.500 239.200 242.720 ;
      LAYER met2 ;
        RECT 5.610 255.050 21.890 255.330 ;
        RECT 22.730 255.050 22.810 255.330 ;
        RECT 23.650 255.050 23.730 255.330 ;
        RECT 24.570 255.050 24.650 255.330 ;
        RECT 25.490 255.050 25.570 255.330 ;
        RECT 26.410 255.050 26.490 255.330 ;
        RECT 27.330 255.050 44.890 255.330 ;
        RECT 45.730 255.050 45.810 255.330 ;
        RECT 46.650 255.050 46.730 255.330 ;
        RECT 47.570 255.050 47.650 255.330 ;
        RECT 48.490 255.050 48.570 255.330 ;
        RECT 49.410 255.050 49.490 255.330 ;
        RECT 50.330 255.050 50.410 255.330 ;
        RECT 51.250 255.050 51.330 255.330 ;
        RECT 52.170 255.050 52.250 255.330 ;
        RECT 53.090 255.050 53.170 255.330 ;
        RECT 54.010 255.050 54.090 255.330 ;
        RECT 54.930 255.050 55.010 255.330 ;
        RECT 55.850 255.050 55.930 255.330 ;
        RECT 56.770 255.050 56.850 255.330 ;
        RECT 57.690 255.050 57.770 255.330 ;
        RECT 58.610 255.050 90.890 255.330 ;
        RECT 91.730 255.050 93.650 255.330 ;
        RECT 94.490 255.050 101.930 255.330 ;
        RECT 102.770 255.050 104.690 255.330 ;
        RECT 105.530 255.050 106.530 255.330 ;
        RECT 107.370 255.050 107.450 255.330 ;
        RECT 108.290 255.050 108.370 255.330 ;
        RECT 109.210 255.050 112.970 255.330 ;
        RECT 113.810 255.050 113.890 255.330 ;
        RECT 114.730 255.050 124.930 255.330 ;
        RECT 125.770 255.050 125.850 255.330 ;
        RECT 126.690 255.050 126.770 255.330 ;
        RECT 127.610 255.050 136.890 255.330 ;
        RECT 137.730 255.050 137.810 255.330 ;
        RECT 138.650 255.050 138.730 255.330 ;
        RECT 139.570 255.050 140.570 255.330 ;
        RECT 141.410 255.050 141.490 255.330 ;
        RECT 142.330 255.050 142.410 255.330 ;
        RECT 143.250 255.050 150.690 255.330 ;
        RECT 151.530 255.050 151.610 255.330 ;
        RECT 152.450 255.050 154.370 255.330 ;
        RECT 155.210 255.050 156.210 255.330 ;
        RECT 157.050 255.050 161.730 255.330 ;
        RECT 162.570 255.050 162.650 255.330 ;
        RECT 163.490 255.050 165.410 255.330 ;
        RECT 166.250 255.050 167.250 255.330 ;
        RECT 168.090 255.050 168.170 255.330 ;
        RECT 169.010 255.050 169.090 255.330 ;
        RECT 169.930 255.050 174.610 255.330 ;
        RECT 175.450 255.050 175.530 255.330 ;
        RECT 176.370 255.050 187.490 255.330 ;
        RECT 188.330 255.050 188.410 255.330 ;
        RECT 189.250 255.050 189.330 255.330 ;
        RECT 190.170 255.050 190.250 255.330 ;
        RECT 191.090 255.050 192.090 255.330 ;
        RECT 192.930 255.050 194.850 255.330 ;
        RECT 195.690 255.050 205.890 255.330 ;
        RECT 206.730 255.050 209.570 255.330 ;
        RECT 210.410 255.050 238.650 255.330 ;
        RECT 5.610 0.560 238.650 255.050 ;
        RECT 5.610 0.280 34.770 0.560 ;
        RECT 35.610 0.280 35.690 0.560 ;
        RECT 36.530 0.280 47.650 0.560 ;
        RECT 48.490 0.280 50.410 0.560 ;
        RECT 51.250 0.280 68.810 0.560 ;
        RECT 69.650 0.280 69.730 0.560 ;
        RECT 70.570 0.280 77.090 0.560 ;
        RECT 77.930 0.280 78.010 0.560 ;
        RECT 78.850 0.280 78.930 0.560 ;
        RECT 79.770 0.280 79.850 0.560 ;
        RECT 80.690 0.280 87.210 0.560 ;
        RECT 88.050 0.280 90.890 0.560 ;
        RECT 91.730 0.280 91.810 0.560 ;
        RECT 92.650 0.280 97.330 0.560 ;
        RECT 98.170 0.280 103.770 0.560 ;
        RECT 104.610 0.280 104.690 0.560 ;
        RECT 105.530 0.280 106.530 0.560 ;
        RECT 107.370 0.280 108.370 0.560 ;
        RECT 109.210 0.280 110.210 0.560 ;
        RECT 111.050 0.280 116.650 0.560 ;
        RECT 117.490 0.280 117.570 0.560 ;
        RECT 118.410 0.280 119.410 0.560 ;
        RECT 120.250 0.280 120.330 0.560 ;
        RECT 121.170 0.280 121.250 0.560 ;
        RECT 122.090 0.280 122.170 0.560 ;
        RECT 123.010 0.280 123.090 0.560 ;
        RECT 123.930 0.280 124.010 0.560 ;
        RECT 124.850 0.280 124.930 0.560 ;
        RECT 125.770 0.280 125.850 0.560 ;
        RECT 126.690 0.280 126.770 0.560 ;
        RECT 127.610 0.280 127.690 0.560 ;
        RECT 128.530 0.280 128.610 0.560 ;
        RECT 129.450 0.280 129.530 0.560 ;
        RECT 130.370 0.280 130.450 0.560 ;
        RECT 131.290 0.280 131.370 0.560 ;
        RECT 132.210 0.280 132.290 0.560 ;
        RECT 133.130 0.280 133.210 0.560 ;
        RECT 134.050 0.280 134.130 0.560 ;
        RECT 134.970 0.280 136.890 0.560 ;
        RECT 137.730 0.280 137.810 0.560 ;
        RECT 138.650 0.280 138.730 0.560 ;
        RECT 139.570 0.280 141.490 0.560 ;
        RECT 142.330 0.280 145.170 0.560 ;
        RECT 146.010 0.280 146.090 0.560 ;
        RECT 146.930 0.280 147.010 0.560 ;
        RECT 147.850 0.280 147.930 0.560 ;
        RECT 148.770 0.280 148.850 0.560 ;
        RECT 149.690 0.280 149.770 0.560 ;
        RECT 150.610 0.280 150.690 0.560 ;
        RECT 151.530 0.280 151.610 0.560 ;
        RECT 152.450 0.280 152.530 0.560 ;
        RECT 153.370 0.280 153.450 0.560 ;
        RECT 154.290 0.280 154.370 0.560 ;
        RECT 155.210 0.280 185.650 0.560 ;
        RECT 186.490 0.280 186.570 0.560 ;
        RECT 187.410 0.280 187.490 0.560 ;
        RECT 188.330 0.280 188.410 0.560 ;
        RECT 189.250 0.280 189.330 0.560 ;
        RECT 190.170 0.280 190.250 0.560 ;
        RECT 191.090 0.280 191.170 0.560 ;
        RECT 192.010 0.280 192.090 0.560 ;
        RECT 192.930 0.280 193.010 0.560 ;
        RECT 193.850 0.280 193.930 0.560 ;
        RECT 194.770 0.280 194.850 0.560 ;
        RECT 195.690 0.280 195.770 0.560 ;
        RECT 196.610 0.280 196.690 0.560 ;
        RECT 197.530 0.280 197.610 0.560 ;
        RECT 198.450 0.280 198.530 0.560 ;
        RECT 199.370 0.280 199.450 0.560 ;
        RECT 200.290 0.280 200.370 0.560 ;
        RECT 201.210 0.280 201.290 0.560 ;
        RECT 202.130 0.280 202.210 0.560 ;
        RECT 203.050 0.280 203.130 0.560 ;
        RECT 203.970 0.280 204.050 0.560 ;
        RECT 204.890 0.280 204.970 0.560 ;
        RECT 205.810 0.280 205.890 0.560 ;
        RECT 206.730 0.280 206.810 0.560 ;
        RECT 207.650 0.280 207.730 0.560 ;
        RECT 208.570 0.280 208.650 0.560 ;
        RECT 209.490 0.280 209.570 0.560 ;
        RECT 210.410 0.280 210.490 0.560 ;
        RECT 211.330 0.280 211.410 0.560 ;
        RECT 212.250 0.280 212.330 0.560 ;
        RECT 213.170 0.280 213.250 0.560 ;
        RECT 214.090 0.280 214.170 0.560 ;
        RECT 215.010 0.280 215.090 0.560 ;
        RECT 215.930 0.280 216.010 0.560 ;
        RECT 216.850 0.280 216.930 0.560 ;
        RECT 217.770 0.280 217.850 0.560 ;
        RECT 218.690 0.280 218.770 0.560 ;
        RECT 219.610 0.280 219.690 0.560 ;
        RECT 220.530 0.280 220.610 0.560 ;
        RECT 221.450 0.280 221.530 0.560 ;
        RECT 222.370 0.280 222.450 0.560 ;
        RECT 223.290 0.280 223.370 0.560 ;
        RECT 224.210 0.280 224.290 0.560 ;
        RECT 225.130 0.280 225.210 0.560 ;
        RECT 226.050 0.280 226.130 0.560 ;
        RECT 226.970 0.280 238.650 0.560 ;
      LAYER met3 ;
        RECT 0.600 232.240 244.290 242.245 ;
        RECT 1.000 230.840 244.290 232.240 ;
        RECT 0.600 222.720 244.290 230.840 ;
        RECT 1.000 221.320 244.290 222.720 ;
        RECT 0.600 203.680 244.290 221.320 ;
        RECT 0.600 194.120 243.890 203.680 ;
        RECT 0.600 176.480 244.290 194.120 ;
        RECT 1.000 175.120 244.290 176.480 ;
        RECT 1.000 172.360 243.890 175.120 ;
        RECT 0.600 169.680 243.890 172.360 ;
        RECT 1.000 168.280 243.890 169.680 ;
        RECT 1.000 166.920 244.290 168.280 ;
        RECT 0.600 162.880 244.290 166.920 ;
        RECT 0.600 160.160 243.890 162.880 ;
        RECT 1.000 160.120 243.890 160.160 ;
        RECT 1.000 157.440 244.290 160.120 ;
        RECT 1.000 156.040 243.890 157.440 ;
        RECT 0.600 154.720 244.290 156.040 ;
        RECT 1.000 150.600 244.290 154.720 ;
        RECT 0.600 146.560 244.290 150.600 ;
        RECT 1.000 141.080 243.890 146.560 ;
        RECT 0.600 137.040 243.890 141.080 ;
        RECT 1.000 135.640 243.890 137.040 ;
        RECT 1.000 132.960 244.290 135.640 ;
        RECT 1.000 130.200 243.890 132.960 ;
        RECT 1.000 127.480 244.290 130.200 ;
        RECT 0.600 123.440 244.290 127.480 ;
        RECT 1.000 120.680 243.890 123.440 ;
        RECT 0.600 119.360 243.890 120.680 ;
        RECT 1.000 117.960 243.890 119.360 ;
        RECT 0.600 116.640 243.890 117.960 ;
        RECT 1.000 109.800 243.890 116.640 ;
        RECT 1.000 108.440 244.290 109.800 ;
        RECT 0.600 104.400 244.290 108.440 ;
        RECT 1.000 100.320 244.290 104.400 ;
        RECT 1.000 97.560 243.890 100.320 ;
        RECT 0.600 94.880 243.890 97.560 ;
        RECT 1.000 92.120 243.890 94.880 ;
        RECT 0.600 88.040 243.890 92.120 ;
        RECT 0.600 86.720 244.290 88.040 ;
        RECT 0.600 83.960 243.890 86.720 ;
        RECT 0.600 81.280 244.290 83.960 ;
        RECT 1.000 75.800 244.290 81.280 ;
        RECT 0.600 71.760 244.290 75.800 ;
        RECT 1.000 69.000 244.290 71.760 ;
        RECT 0.600 64.960 244.290 69.000 ;
        RECT 1.000 63.600 244.290 64.960 ;
        RECT 1.000 62.200 243.890 63.600 ;
        RECT 0.600 48.640 244.290 62.200 ;
        RECT 1.000 47.240 244.290 48.640 ;
        RECT 0.600 43.200 244.290 47.240 ;
        RECT 1.000 41.800 244.290 43.200 ;
        RECT 0.600 40.480 244.290 41.800 ;
        RECT 0.600 39.080 243.890 40.480 ;
        RECT 0.600 10.715 244.290 39.080 ;
      LAYER met4 ;
        RECT 176.935 19.895 177.540 118.825 ;
        RECT 179.940 19.895 226.945 118.825 ;
  END
END axi2apb_bridge
END LIBRARY

